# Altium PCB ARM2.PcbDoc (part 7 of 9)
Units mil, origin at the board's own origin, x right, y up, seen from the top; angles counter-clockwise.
Board outline 4700.79 x 3937.01 mil, 6 copper layers (Top Layer, GND02, ART03, ART04, PWR05, Bottom Layer); 689 components, 508 nets, 2312 pads, 1231 vias.

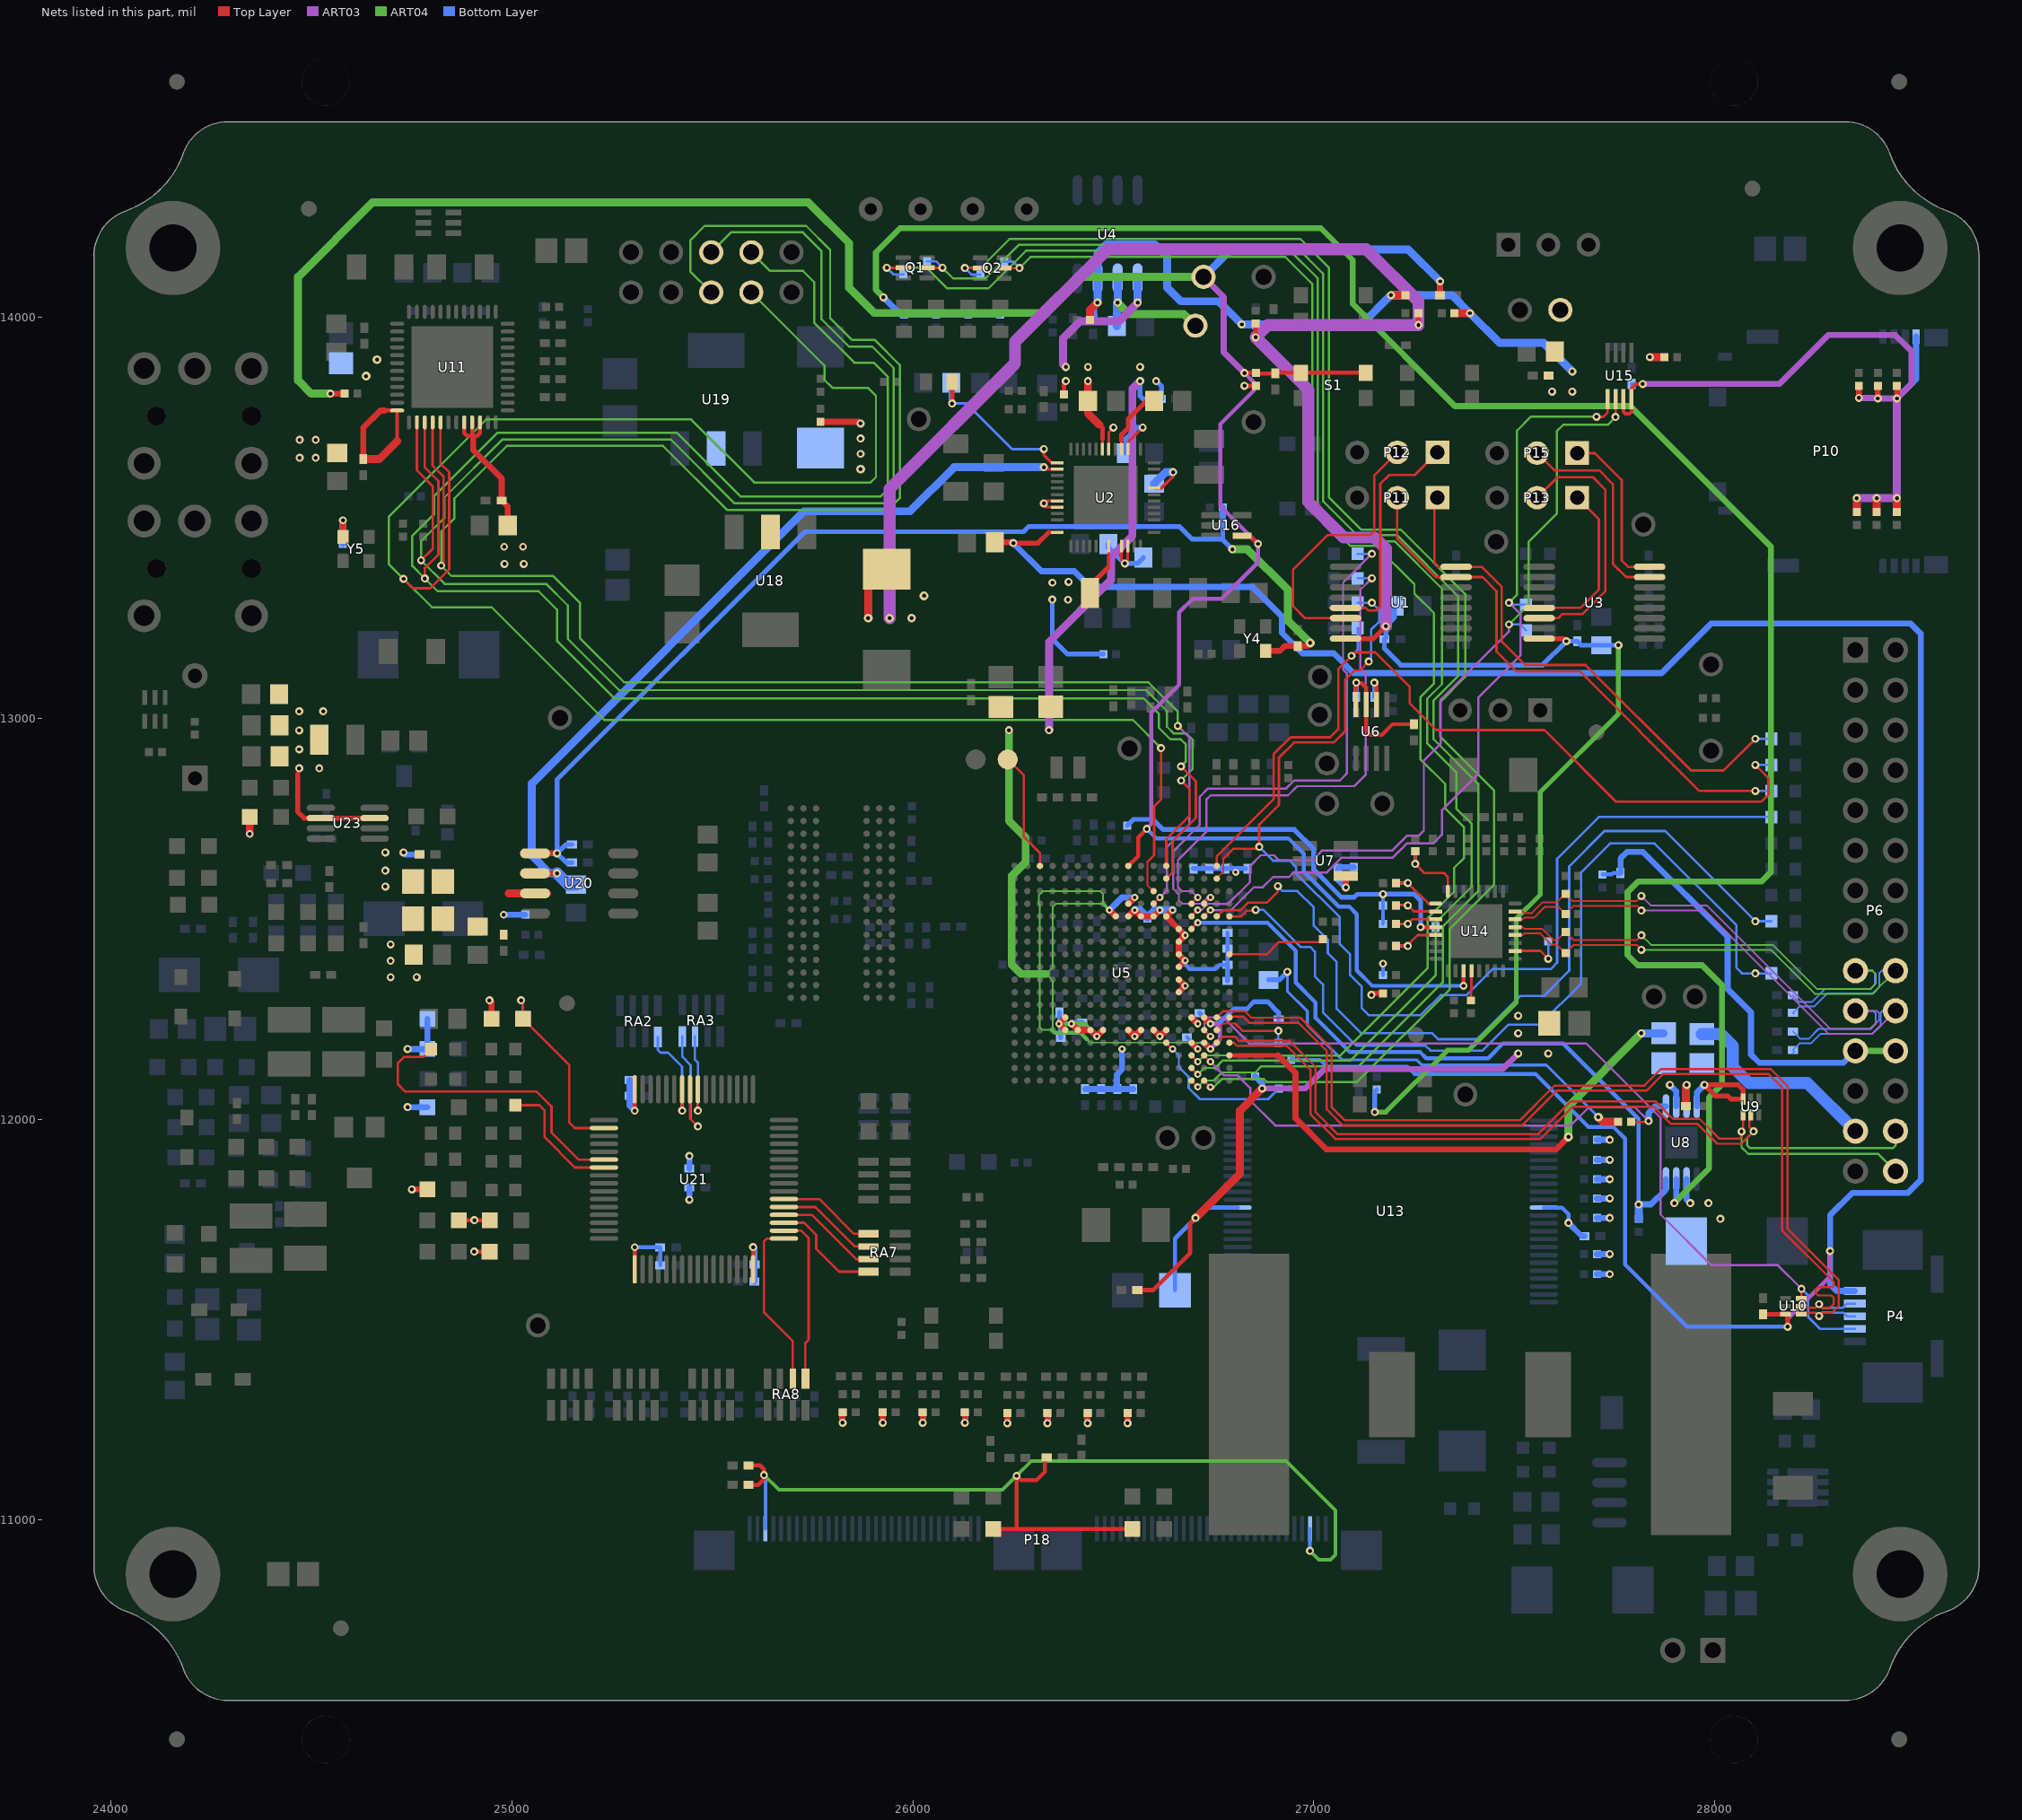
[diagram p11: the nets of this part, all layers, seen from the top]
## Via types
v1: diameter 20, hole 10, Top Layer to Bottom Layer, tented both sides, 870 vias
v2: diameter 18, hole 8, Top Layer to Bottom Layer, tented both sides, 273 vias
v3: diameter 22, hole 10, Top Layer to Bottom Layer, tented both sides, 64 vias
v4: diameter 20, hole 10, Top Layer to Bottom Layer, 18 vias
v5: diameter 22, hole 12, Top Layer to Bottom Layer, 4 vias
v6: diameter 22, hole 10, Top Layer to Bottom Layer, 1 vias
v7: diameter 39.37, hole 19.68, Top Layer to Bottom Layer, tented both sides, 1 vias

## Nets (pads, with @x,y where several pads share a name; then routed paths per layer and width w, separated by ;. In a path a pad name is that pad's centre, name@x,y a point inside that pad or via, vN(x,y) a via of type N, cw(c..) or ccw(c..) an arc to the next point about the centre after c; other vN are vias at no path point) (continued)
RI_H3: RA2.5 U21.58 | length 272.9
  Top Layer w6: v1(25424.84,12021.21) U21.58@25424.84,12074.41
  Bottom Layer w6: RA2.5@25364.24,12204.63 25364.24,12172.76 25371,12166 25390,12166 25424.84,12131.16 v1(25424.84,12021.21)
RI_H4: RA3.8 U21.57 | length 341.2
  Top Layer w6: U21.57@25444.53,12074.41 25444.53,12001.52 v1(25464.21,11981.84)
  Bottom Layer w6: RA3.8@25425.51,12206.26 25425.51,12155.49 25446,12135 25446,12000.05 v1(25464.21,11981.84)
RI_H5: RA3.7 U21.56 | length 241.2
  Top Layer w6: v1(25464.21,12021.21) U21.56@25464.21,12074.41
  Bottom Layer w6: RA3.7@25457.01,12206.26 25457.01,12148.52 25464.21,12141.32 v1(25464.21,12021.21)
RLH: R195.2 U21.7 | length 324.5
  Top Layer w6: R195.2@25008.92,12035 25068.62,12035 25082,12021.62 25082,11955 25157.47,11879.53 U21.7@25229.96,11879.53
RO_H0: RA7.1 U21.38 | length 246.7
  Top Layer w6: U21.38@25678.78,11800.79 25766.72,11800.79 25853.27,11714.24 RA7.1@25889.63,11714.24
RO_H1: RA7.2 U21.37 | length 251.6
  Top Layer w6: U21.37@25678.78,11781.1 25757.38,11781.1 25855.73,11682.75 RA7.2@25889.63,11682.75
RO_H2: RA7.3 U21.36 | length 256.5
  Top Layer w6: U21.36@25678.78,11761.42 25748.58,11761.42 25858.75,11651.25 RA7.3@25889.63,11651.25
RO_H3: RA7.4 U21.35 | length 281.4
  Top Layer w6: U21.35@25678.78,11741.73 25728.82,11741.73 25759.53,11711.02 25759.53,11676.77 25816.54,11619.76 RA7.4@25889.63,11619.76
RO_H4: RA8.1 U21.34 | length 423.2
  Top Layer w6: U21.34@25678.78,11722.05 25722.09,11722.05 25740.27,11703.87 25740.27,11449.9 25732.24,11441.87 RA8.1@25732.24,11352.99
RO_H5: RA8.2 U21.33 | length 424.6
  Top Layer w6: U21.33@25678.78,11702.36 25636,11702.36 25629.15,11695.51 25629.15,11517.48 25700.75,11445.87 RA8.2@25700.75,11352.99
RS232_0_RXD: P13.1 U3.13 | length 419.3
  Top Layer w6: U3.13@27562.07,13275.19 27665.19,13275.19 27711,13321 27711,13496 P13.1@27657,13550
RS232_0_TXD: P13.2 U3.14 | length 650.4
  Top Layer w6: P13.2@27557,13550 27608,13601 27696,13601 27727,13570 27727,13316 27671,13260 27620.4,13260 27610,13249.6 U3.14@27562.07,13249.6
RS232_1_RXD: P11.1 R248.1 U1.8 | length 1333.1
  Top Layer w6: P11.1@27308.26,13550 27301,13542.74 27301,13388 27311.45,13377.55 U1.8@27355,13377.55 27419.07,13377.55 27469,13327.62 27469,13190.62 27527,13132.62 27677.85,13132.62 27940.96,12869.52 28022.15,12869.52 v1(28101.26,12948.62)
  Bottom Layer w6: v1(28101.26,12948.62) R248.1@28141.34,12948.62
RS232_1_TXD: P11.2 R250.1 U1.7 | length 1387
  Top Layer w6: P11.2@27210.82,13550 P11.2@27208.26,13550 27208.26,13447.44 27303.74,13351.96 U1.7@27355,13351.96 27420.66,13351.96 27456,13316.62 27456,13165.89 27505.27,13116.62 27663.47,13116.62 27961.47,12818.62 v1(28101.26,12818.62)
  Bottom Layer w6: v1(28101.26,12818.62) R250.1@28141.34,12818.62
RS232_2_RXD: P12.1 U1.13 | length 573.5
  Top Layer w6: U1.13@27079.41,13275.19 27129.32,13275.19 27135.57,13268.94 27155.86,13268.94 27166,13279.08 27166,13584.45 27188.12,13606.57 27251.83,13606.57 P12.1@27308.26,13663
RS232_2_TXD: P12.2 U1.14 | length 698.8
  Top Layer w6: U1.14@27081.01,13248 U1.14@27079.41,13249.6 26978.4,13249.6 26948,13280 26948,13369.45 27035.55,13457 27141,13457 27151,13467 27151,13605.74 P12.2@27208.26,13663
RS232_5_RXD: P15.1 U3.8 | length 415.8
  Top Layer w6: P15.1@27657,13661 27701,13661 27768,13594 27768,13393 27783.45,13377.55 U3.8@27837.66,13377.55
RS232_5_TXD: P15.2 U3.7 | length 525.2
  Top Layer w6: P15.2@27557,13661 27600,13618 27712,13618 27746,13584 27746,13385 27779.04,13351.96 U3.7@27837.66,13351.96
RXD0/MODE0: R112.1 R128.2 U14.11 | length 136.9
  Top Layer w6: R128.2@27205,12487.33 v1(27234.67,12487.33) ; v1@27235.88,12488.55 v1(27234.67,12487.33) ; U14.11@27302.89,12497.33 U14.11@27304.11,12498.55 27245.88,12498.55 v1(27234.67,12487.33)
  Bottom Layer w6: R112.1@27205,12487.33 v1(27234.67,12487.33)
RXD1/MODE1: R114.1 R127.2 U14.10 | length 135
  Top Layer w6: R127.2@27205,12533.17 v1(27234.67,12533.17) 27249.58,12518.25 U14.10@27304.11,12518.25
  Bottom Layer w6: R114.1@27205,12533.17 v1(27234.67,12533.17)
RXD2/RMIISEL: R117.1 R126.2 U14.9 | length 150.3
  Top Layer w6: R126.2@27205,12589 v1(27234.67,12589) 27286.67,12537 U14.9@27304.11,12537
  Bottom Layer w6: R117.1@27205,12589 v1(27234.67,12589)
RXD3/PHYAD2: R116.1 R125.2 U14.8 | length 203.6
  Top Layer w6: R125.2@27253.11,12667.86 v1(27253.11,12636.6) 27275.71,12614 27290,12614 ; 27280,12614 27290,12614 ; U14.8@27334.16,12568 27334.16,12604.84 27325,12614 27290,12614
  Bottom Layer w6: v1(27253.11,12636.6) R116.1@27253.11,12667.86
RXDV: R129.2 U14.26 | length 133.9
  Top Layer w6: U14.26@27502.11,12419.75 27565.25,12419.75 v1(27585,12400)
  Bottom Layer w6: v1(27585,12400) R129.2@27585,12442.86
RXER/PHYAD0: R115.1 R133.2 U14.13 | length 139
  Top Layer w6: R133.2@27205,12432 v1(27234.67,12432) ; v1@27234.67,12434.5 27259.32,12459.15 U14.13@27304.11,12459.15
  Bottom Layer w6: R115.1@27205,12432 v1(27234.67,12432)
RXN: C138.1 P6.20 R121.1 U14.30 | length 1453.3
  Top Layer w4.4: U14.30@27502.11,12498.55 27521,12498.55 27524.9,12502.45 27548.93,12502.45 27575.58,12529.1 27610.62,12529.1 R121.1@27627.72,12512 27647.62,12531.91 27805.65,12531.91 v1(27817.12,12520.43)
  ART03 w4.3: v1(27817.12,12520.43) 27976.05,12520.43 28283.24,12213.23 28393.9,12213.23 P6.20@28450.94,12270.28
  Bottom Layer w4.4: C138.1@28195,12165 C138.1@28198.9,12168.9 ; C138.1@28195,12172.8 28211.26,12189.06 28239.75,12189.06 28263.92,12213.23 28392.89,12213.23 28413.78,12234.12 28413.78,12266.51 28417.55,12270.28 P6.20@28450.94,12270.28
RXP: C137.1 P6.19 R120.1 U14.31 | length 1475.1
  Top Layer w4.4: U14.31@27502.11,12518.25 27521,12518.25 27524.9,12514.35 27544,12514.35 27570.65,12541 27606.72,12541 R120.1@27627.72,12562 27645.91,12543.81 27804.36,12543.81 v1(27817.12,12556.57)
  ART03 w4.3: v1(27817.12,12556.57) 27840.97,12532.73 27981.14,12532.73 28288.34,12225.53 28388.8,12225.53 28409.73,12246.45 28409.73,12265.07 28404.52,12270.28 P6.19@28350.94,12270.28
  Bottom Layer w4.4: C137.1@28195,12218.62 28212.67,12200.96 28234.82,12200.96 28258.99,12225.13 28387.96,12225.13 28401.88,12239.05 28401.88,12263.17 28394.78,12270.28 P6.19@28350.94,12270.28
SEL_I_DATA: R202.2 R207.1 U21.2 | length 495.7
  Top Layer w6: v1(25023.37,12296.63) 25028.37,12291.63 R202.2@25028.37,12250 25143,12135.37 25143,11992 25157.05,11977.95 U21.2@25229.96,11977.95
  Bottom Layer w6: v1(25023.37,12296.63) 25028.37,12291.63 R207.1@25028.37,12250
SPI1_CS0: TP25.1 U5.C12 U11.41 | length 5157.1
  Top Layer w4.4: 26585.12,12641.57 26585.12,12584.32 U5.C12@26600.72,12568.72
  Top Layer w6: v1(24730.12,13347.57) 24753.58,13324.12 24796.67,13324.12 24844,13371.45 24844,13613.62 24822.06,13635.57 24822.06,13737.41 U11.41@24822.47,13737.82 ; 26585.12,12641.57 26602.12,12658.57 26602.12,12780.3 26619.12,12797.3 v1(26619.12,12925.57)
  ART04 w5.5: TP25.1@25597.5,14062 25780.07,13879.43 25780.07,13843.6 25799.78,13823.89 25888.05,13823.89 25908.19,13803.76 25908.19,13601.12 25894.82,13587.75 25604.7,13587.75 25447.56,13744.89 24936.44,13744.89 24693.12,13501.57 24693.12,13384.57 v1(24730.12,13347.57) 24801.19,13276.51 24950.19,13276.51 25231.12,12995.57 26549.12,12995.57 v1(26619.12,12925.57)
SPI1_D0: TP26.1 U5.B13 U11.39 | length 5258.4
  Top Layer w6: v1(24783.12,13348.62) 24783.12,13374.57 24817,13408.45 24817,13591.62 24783.1,13625.52 U11.39@24783.1,13737.82 ; U5.B13@26632.22,12600.22 26648.02,12616.02 26648.02,12692.87 26706.12,12750.97 26706.12,12842.58 v1(26668.9,12879.8)
  ART04 w5.5: TP26.1@25597.5,14162 25643.93,14115.57 25726.37,14115.57 25754.18,14087.76 25754.18,13986.52 25854.11,13886.59 25902.86,13886.59 25938.04,13851.41 25938.04,13571.01 25919.41,13552.38 25571.44,13552.38 25412.45,13711.38 24963.8,13711.38 24806.12,13553.7 24806.12,13508.57 24752.12,13454.57 24752.12,13379.62 v1(24783.12,13348.62) 24815.44,13316.31 25067.17,13316.31 25112.64,13270.84 25112.64,13193.05 25256.2,13049.5 26575.8,13049.5 26613.53,13011.77 26613.53,12976.59 26642.55,12947.57 26668.12,12947.57 26681.12,12934.57 26681.12,12892.03 v1(26668.9,12879.8)
SPI1_D1: TP27.1 U5.D12 U11.40 | length 5625.4
  Top Layer w6: U11.40@24802.79,13737.82 24802.79,13629.83 24830,13602.62 v1@24830,13380.57 ; U5.D12@26600.72,12537.23 v2(26616.47,12552.98)
  ART03 w5.5: v2(26616.47,12552.98) 26634.12,12570.64 26634.12,12679.57 26690.12,12735.57 26690.12,12951.57 v1(26661.12,12980.57)
  ART04 w5.5: TP27.1@25497.5,14062 25445.12,14114.38 25445.12,14191.57 25481.12,14227.57 25734.11,14227.57 25794.1,14167.59 25794.1,13997.6 25847.88,13943.82 25904.88,13943.82 25967.88,13880.81 25967.88,13548.66 25938.77,13519.55 25536.93,13519.55 25377.05,13679.42 24987.98,13679.42 24857.06,13548.51 24857.06,13498.64 24824.12,13465.7 v1(24824.12,13380.57) 24850.17,13354.53 25103.35,13354.53 25170.7,13287.19 25170.7,13199 25280.1,13089.6 26587.83,13089.6 26661.12,13016.31 v1(26661.12,12980.57)
SPI1_SCLK: TP28.1 U5.A13 U11.38 | length 5378.3
  Top Layer w6: U11.38@24763.42,13737.82 24763.42,13618.2 24803.21,13578.41 24803.21,13422.83 v1(24774,13393.62) ; U5.A13@26632.22,12631.72 26632.22,12698.39 26690.12,12756.3 26690.12,12823.72 v1(26669.32,12844.53)
  ART04 w5.5: TP28.1@25497.5,14162 25547.07,14211.57 25725.9,14211.57 25772.75,14164.72 25772.75,13994.95 25841.12,13926.57 25899.12,13926.57 25952.7,13873 25952.7,13560.87 25927.56,13535.73 25555.87,13535.73 25396.31,13695.29 24976.84,13695.29 24832.17,13550.62 24832.17,13499.53 24774,13441.36 v1(24774,13393.62) 24832.58,13335.04 25085.81,13335.04 25139.92,13280.93 25139.92,13197.78 25267.64,13070.06 26581.91,13070.06 26633.87,13018.1 26633.87,12978.83 26651.12,12961.57 26682.88,12961.57 26697.67,12946.79 26697.67,12872.88 v1(26669.32,12844.53)
SYS_5V: C7.2 C8.2 C10.2 C13.2 C17.1 C34.1 C200.1 R71.1 R72.1 R73.1 R74.1 TP12.1 U2.2 U2.7 U2.8 U2.21 U2.22 U2.32 U2.39 U2.42 U4.2 U8.2 U8.3 U20.2 | length 8396.9
  Top Layer w7: v1(26327,13626) 26332.13,13620.87 U2.2@26359.99,13620.87 ; U2.8@26359.99,13526.38 26331.62,13526.38 26327,13531 v1(26327,13536) 26333.13,13542.13 U2.7@26359.99,13542.13 ; U2.42@26488.92,13671.06 26488.92,13713.42 v1(26500.44,13724.93) ; U2.21@26520.42,13428.94 26520.42,13394.58 v1(26529,13386) 26536.17,13393.17 U2.22@26536.17,13428.94 ; U2.39@26536.42,13671.31 U2.39@26536.17,13671.06 26536.17,13687.67 v1(26573.44,13724.93)
  Top Layer w8: U2.32@26602.12,13573.62 26619.71,13573.62 26649.35,13603.26 v1(26649.35,13613.82)
  Top Layer w15: U20.2@25058,12613 v1(25113,12613)
  ART04 w15: v1(25927.12,14049.57) 25908.12,14068.57 25908.12,14161.57 25968.52,14221.97 27017.73,14221.97 27097.12,14142.57 27097.12,14033.57 27352.12,13778.57 27789.12,13778.57 28140.37,13427.32 28140.37,12616.72 28116.22,12592.57 27808.67,12592.57 27782.47,12566.36 27782.47,12409.13 27807.69,12383.91 27968.47,12383.91 28018.44,12333.94 28018.44,12087.36 27985.71,12054.64 27985.71,11877.16 v1(27899.12,11790.57)
  ART04 w20: v1(26510.92,14036.78) 26540.12,14007.57 26676.38,14007.57 TP12.1@26705,13978.95
  Bottom Layer w12: C8.2@26487.44,13433.94 26487.44,13425.57 26528,13385 v1(26529,13386) 26560.55,13386 C7.2@26575.12,13400.57 ; C13.2@26532,13661 26532,13698.34 26558.6,13724.93 v1(26573.44,13724.93)
  Bottom Layer w15: v1(25927.12,14049.57) 25969.84,14006.86 R72.1@25978.19,14006.86 R73.1@26058.19,14006.86 R74.1@26138.19,14006.86 R71.1@26218.19,14006.86 ; v1(27899.12,11790.57) 27904,11795.45 U8.3@27904,11850.37 ; U8.2@27929.6,11850.37 27929.6,11800.1 v1(27939.12,11790.57)
  Bottom Layer w20: v1(25113,12613) 25094.15,12613 25050,12657.15 25050,12837.05 25728.96,13516.01 25993.09,13516.01 26103.08,13626 v1(26327,13626) ; C17.1@26509.54,13977.88 26509.54,14035.41 v1(26510.92,14036.78) U4.2@26510.92,14096.88 ; C10.2@26602,13585 26630.82,13613.82 v1(26649.35,13613.82)
  Bottom Layer w30: v1(25113,12613) 25141,12585 C200.1@25160,12585
  other v1: 28014.12,11751.57 27984.12,11790.57
SYS_RESETN: C24.1 C30.1 R14.2 R44.1 S1.2 S1.4 TP14.1 U5.A10 U14.19 U16.4 | length 6846.6
  Top Layer w10: U5.A10@26537.73,12631.72 26562.12,12656.12 26562.12,12702.62 v1(26583.56,12724.06) ; R14.2@26855.73,13861.14 26856.87,13860 C24.1@26903.73,13860 26905.23,13861.5 S1.2@26968.02,13861.5 S1.4@27129.44,13861.5 ; v1(27373.56,12332.56) U14.19@27373.56,12370
  Top Layer w12: U16.4@26821.37,13455.41 26840.41,13455.41 v1(26861,13434.82) ; v1(26827.14,13861.14) R14.2@26855.73,13861.14
  Top Layer w15: v1(24548,13809.41) R44.1@24582.86,13809.41 ; C30.1@27315,14055 v1(27315,14089.45)
  ART03 w10: v1@26583,12724.62 v1@26583.56,12725.18 ; v1(26583.56,12724.06) v1@26583.56,12725.18 ; v1(26827.14,13861.14) 26851.12,13837.16 26851.12,13817.57 26767.12,13733.57 26767.12,13528.69 v1(26861,13434.82) 26861,13388.45 26770.55,13298 26698.12,13298 26664.2,13264.07 26664.2,13083.5 26595.12,13014.43 26595.12,12736.75 v1@26583.56,12725.18
  ART03 w15: TP14.1@26725.12,14100.57 26775.63,14050.06 26775.63,13912.65 v1(26827.14,13861.14)
  ART04 w20: v1(24548,13809.41) 24500.28,13809.41 24467.12,13842.57 24467.12,14100.57 24653.12,14286.57 25739.12,14286.57 25841.12,14184.57 25841.12,14073.57 25904.12,14010.57 26325.12,14010.57 26415.12,14100.57 TP14.1@26725.12,14100.57
  Bottom Layer w10: v1@26583,12724.62 v1(26583.56,12724.06) 26607.07,12700.55 26936.45,12700.55 26975,12662 26975,12617.67 27062.68,12529.99 27088.63,12529.99 27107.59,12511.03 27107.59,12371.03 27146.06,12332.56 v1(27373.56,12332.56)
  Bottom Layer w20: TP14.1@26725.12,14100.57 26793.66,14169.11 27235.34,14169.11 v1(27315,14089.45)
TCT_RCT: C141.1 P6.21 P6.22 R137.1 | length 1149.3
  ART04 w15: P6.21@28350.94,12170.28 P6.22@28450.94,12170.28
  Bottom Layer w10: R137.1@27720,12610.14 27743,12610.14 27746.86,12614 C141.1@27765,12614 C141.1@27761.14,12610.14
  Bottom Layer w15: C141.1@27765,12614 27765,12650 27781.62,12666.62 27821,12666.62 28032,12455.62 28032,12324.7 28090.12,12266.57 28090.12,12161.57 28111.12,12140.57 28321.24,12140.57 P6.21@28350.94,12170.28
TESTOUT: TP3.1 U5.A3 | length 298.5
  Top Layer w6: TP3.1@26237,12897 26277,12857 26277,12704 26317.26,12663.74 U5.A3@26317.26,12631.72
TXCLK: R134.2 U14.20 | length 74.4
  Top Layer w6: R134.2@27391.88,12296.2 27391.88,12319.25 27393.26,12320.62 U14.20@27393.26,12370
TXN: C140.1 P6.18 R123.1 U14.28 | length 1380.1
  Top Layer w4.4: U14.28@27502.11,12459.15 27521,12459.15 27524.9,12463.05 27564.95,12463.05 27592.9,12435.1 27606.62,12435.1 R123.1@27627.72,12414 27648.27,12434.55 27805,12434.55 v1(27817.12,12422.43)
  ART04 w4.3: v1(27817.12,12422.43) v1@27817.24,12422.31 ; v1@27819.28,12420.27 v1@27817.24,12422.31 ; P6.18@28450.94,12370.28 28393.5,12312.83 28249.45,12312.83 28139.97,12422.31 v1@27817.24,12422.31
  Bottom Layer w4.4: C140.1@28197.33,12262.67 C140.1@28195,12265 28210.86,12280.86 28247.99,12280.86 28280.36,12313.23 28394.8,12313.23 28410.87,12329.3 28410.87,12364.93 28416.21,12370.28 P6.18@28450.94,12370.28
TXP: C139.1 P6.17 R122.1 U14.29 | length 1381.7
  Top Layer w4.4: U14.29@27502.11,12478.85 27521,12478.85 27524.9,12474.95 27569.88,12474.95 27597.83,12447 27607.72,12447 R122.1@27627.72,12467 27648.27,12446.45 27805,12446.45 v1(27817.12,12458.57)
  ART04 w4.3: v1(27817.12,12458.57) 27841.09,12434.61 28145.06,12434.61 28254.55,12325.13 28388.33,12325.13 28401.92,12338.71 28401.92,12361.72 28393.36,12370.28 P6.17@28350.94,12370.28
  Bottom Layer w4.4: C139.1@28195,12308.62 28210.86,12292.76 28243.06,12292.76 28275.43,12325.13 28389.87,12325.13 28398.97,12334.23 28398.97,12364.66 28393.36,12370.28 P6.17@28350.94,12370.28
U5_H18: R28.1 U5.H18 | length 248.8
  Top Layer w6: U5.H18@26789.7,12411.24 26882.62,12411.24 26913.14,12441.76 27015.23,12441.76 R28.1@27022.72,12449.24
U5_R13: R160.1 U5.R13 | length 383.6
  Top Layer w6: U5.R13@26632.22,12190.77 v2(26647.97,12175.03)
  Bottom Layer w4.4: v2(26647.97,12175.03) 26663.47,12159.53 26663.47,12130.16
  Bottom Layer w6: 26663.47,12130.16 26688,12105.62 26688,12077.67 26715.67,12050 26886.31,12050 R160.1@26912.92,12076.61
UART0_RXD: R42.1 U5.E15 U15.6 | length 2088.8
  Top Layer w6: U5.E15@26695.21,12505.73 v2(26710.96,12521.48) ; v1(27752.83,13751.46) U15.6@27752.78,13795.57
  ART03 w4.4: v2(26710.96,12521.48) 26720.53,12521.48 26736.28,12537.23 26749.39,12537.23
  ART03 w5.5: 26749.39,12537.23 26786.78,12537.23 26841.12,12591.57 26841.12,12631.57 26867.78,12658.22 26900.48,12658.22 26912.83,12645.87 26996.42,12645.87 27020.12,12669.57 27195.12,12669.57 27232.12,12706.57 27261.17,12706.57 27274.55,12719.96 27274.55,12894.29 27317,12936.74 27317,13047 27487,13217 v1(27487,13234)
  ART04 w5.5: v1(27487,13234) 27536.12,13283.12 27536.12,13440.12 27606,13510 27606,13715.45 27622.12,13731.57 27732.94,13731.57 v1(27752.83,13751.46)
  Bottom Layer w6: v1@27487.06,13234.06 27514.28,13234.06 R42.1@27529.28,13219.06
UART0_TXD: R240.1 U5.E16 U15.5 | length 2109.2
  Top Layer w6: U5.E16@26726.7,12505.73 v2(26742.45,12521.48) ; v1(27705.31,13751.57) 27722.31,13751.57 27733.1,13762.36 U15.5@27733.1,13795.57
  ART03 w5.5: v2(26742.45,12521.48) 26794.03,12521.48 26850.92,12578.36 26872.92,12578.36 26898.62,12604.07 26938.62,12604.07 26950.12,12615.57 27033.12,12615.57 27070.12,12652.57 27197.12,12652.57 27232.12,12687.57 27297.98,12687.57 27319.73,12709.33 27319.73,12770.46 27411,12861.73 27411,13052 27516,13157 27516,13259 v1(27487,13288)
  ART04 w5.5: v1(27487,13288) 27507,13308 27507,13717.45 27541.12,13751.57 v1(27705.31,13751.57)
  Bottom Layer w6: v1@27487.13,13287.87 27492.13,13282.87 R240.1@27529.28,13282.87
UART1_RXD: R244.1 U5.D16 | length 1410.4
  Top Layer w6: U5.D16@26726.7,12537.23 v2(26742.45,12552.98)
  ART03 w4.4: 26649.12,12574.57 26663.47,12560.23 26663.47,12547.05 26673.04,12537.48 26719.48,12537.48 26734.98,12552.98 v2(26742.45,12552.98)
  ART03 w5.5: 26649.12,12574.57 26649.12,12667.57 26715.62,12734.07 26715.62,12804.07 26736.12,12824.57 26931.12,12824.57 26951.12,12844.57 27065.12,12844.57 27083.12,12862.57 27083.12,13111.57 27073.12,13121.57 27073.12,13338.12 v1(27145,13410)
  Bottom Layer w6: R244.1@27109.85,13410 v1(27145,13410)
UART1_TXD: R243.1 U5.D15 | length 1295.4
  Top Layer w6: U5.D15@26695.21,12537.23 v2(26710.96,12552.98)
  ART03 w4.4: 26661.36,12578.77 26671.6,12568.53 26695.65,12568.53 26711.08,12553.1 v2@26711.2,12552.98
  ART03 w5.5: 26661.36,12578.77 26661.36,12645.81 26732.12,12716.57 26732.12,12796.57 26743.12,12807.57 26936.12,12807.57 26959.12,12830.57 27101.12,12830.57 27129.12,12858.57 27129.12,13110.57 27116.12,13123.57 27116.12,13320 v1(27145,13348.87)
  Bottom Layer w6: R243.1@27109.85,13348.87 v1(27145,13348.87)
UART2_RXD: R33.1 R247.1 U5.A17 | length 2153.5
  Top Layer w6: U5.A17@26758.2,12631.72 26758.2,12655.97 26900.12,12797.89 26900.12,12910.52 26942.3,12952.7 27041.01,12952.7 27061.12,12972.82 27061.12,13122.57 v1(27094.12,13155.57) 27102.52,13163.97 27153.73,13163.97 27239.12,13078.57 27239.12,13037.57 27306.12,12970.57 27575.12,12970.57 27754.08,12791.62 28116,12791.62 28134,12809.62 28134,12850.88 v1(28101.26,12883.62)
  Bottom Layer w6: v1(27094.12,13155.57) 27109.85,13171.3 R33.1@27109.85,13225 ; v1(28101.26,12883.62) R247.1@28141.34,12883.62
UART2_TXD: R242.1 R249.1 U5.B17 | length 2917.2
  Top Layer w4.4: U5.B17@26758.2,12600.22 26774,12616.02 26774,12649.07
  Top Layer w6: 26774,12649.07 26799.2,12674.27 26859.05,12674.27 v1(26864.03,12679.25) 26864.03,12734.66 26913,12783.63 26913,12901.6 26950.74,12939.35 27049.96,12939.35 27078.25,12967.64 27078.25,13095.7 27101.12,13118.57 27114.12,13118.57 v1(27137.12,13141.57)
  Bottom Layer w6: v1(26864.03,12679.25) 26898.34,12644.95 26939.73,12644.95 26956.06,12628.61 26956.06,12612.61 27064.99,12503.69 27064.99,12436.34 27090.61,12410.71 27090.61,12359.06 27119.61,12330.06 27119.61,12277.06 27137.06,12259.61 27267.07,12259.61 27316.89,12309.42 27380.56,12309.42 27445.38,12374.25 27590.92,12374.25 27607,12390.32 27607,12649.62 27711,12753.62 R249.1@28141.34,12753.62 ; R242.1@27109.85,13287.87 v1(27145,13287.87) 27163.86,13269.02 27163.86,13241.58 27143.1,13220.82 27143.1,13147.55 v1(27137.12,13141.57)
UART4_RXD: R256.1 U5.E18 | length 2153.9
  Top Layer w6: U5.E18@26789.7,12505.73 26819.52,12505.73 26834.11,12520.33 26854.99,12520.33 26855.11,12520.44 v1(26855.11,12521.94)
  Bottom Layer w6: v1(26855.11,12521.94) 26874.75,12521.94 26967.22,12429.47 26991,12429.47 27003,12417.47 27003,12355.93 27023.15,12335.77 27023.15,12266.47 27106.01,12183.61 27278.39,12183.61 27291.06,12170.94 27420.71,12170.94 27485.67,12235.9 27564.28,12235.9 27667,12338.62 27667,12615.62 27739,12687.62 27850,12687.62 28054,12483.62 28054,12377.62 28068,12363.62 v1(28101.26,12363.62) R256.1@28141.34,12363.62
UART4_TXD: R252.1 U5.E17 | length 2156.1
  Top Layer w6: U5.E17@26758.2,12505.73 26759.1,12505.73 26774.4,12521.03 26816.8,12521.03 26835.71,12539.94 26882.67,12539.94 26910.65,12567.93 v1(26910.65,12581.15)
  Bottom Layer w6: v1(26910.65,12581.15) 26910.65,12580.83 26922.49,12569 26959.28,12569 27000,12528.28 27000,12482.62 27034.88,12447.75 27034.88,12413.88 27057.19,12391.56 27057.19,12275.05 27117.63,12214.61 27294.86,12214.61 27310.06,12199.41 27406.67,12199.41 27514.68,12307.42 27574.25,12307.42 27637,12370.17 27637,12630.62 27725,12718.62 27876.26,12718.62 v1(28101.26,12493.62) R252.1@28141.34,12493.62
UDH: R192.2 U21.6 | length 780.4
  Top Layer w6: R192.2@24799.08,12175 24779.08,12155 24731,12155 24716,12140 24716,12087 24734,12069 25062,12069 25099,12032 25099,11967 25166.79,11899.21 U21.6@25229.96,11899.21
USB0_DM: P4.2 U5.N18 U10.2 | length 2501.5
  Top Layer w5.5: U5.N18@26789.7,12253.76 26792.34,12256.4 26823.4,12256.4 26839.14,12240.66 26961.89,12240.66 27032.4,12170.15 27032.4,12024.54 27072.19,11984.75 27519.31,11984.75 27605.71,12071.15 27829.39,12071.15 27870.87,12112.63 28134.04,12112.63 28168.54,12078.14 28168.54,11721.9 28296.97,11593.47 28296.97,11585.04 28292.92,11580.99 28258.12,11580.99 28251.97,11574.84 28251.97,11566.64 28258.12,11560.49 28290.82,11560.49 28296.97,11554.34 28296.97,11539.44 28287.57,11530.04 28268.55,11530.04 v1(28259.97,11538.62) 28251.47,11530.12 28232.29,11530.12 28229.57,11532.84 U10.2@28218.65,11532.84
  Bottom Layer w5.5: v1(28259.97,11538.62) 28268.47,11530.12 28320.05,11530.12 28330.05,11540.12 P4.2@28349.64,11540.12
USB0_DP: P4.3 U5.N17 U10.1 | length 2503
  Top Layer w5.5: U5.N17@26758.2,12253.76 26773.34,12268.9 26828.58,12268.9 26844.32,12253.16 26967.07,12253.16 27044.9,12175.33 27044.9,12029.72 27077.37,11997.25 27514.13,11997.25 27600.53,12083.65 27824.21,12083.65 27865.69,12125.13 28139.22,12125.13 28181.04,12083.31 28181.04,11727.08 28309.47,11598.65 28309.47,11534.26 28292.75,11517.54 28268.39,11517.54 v1(28259.97,11509.12) 28251.47,11517.62 28233.15,11517.62 28228.69,11513.16 U10.1@28218.65,11513.16
  Bottom Layer w5.5: v1(28259.97,11509.12) 28268.47,11517.62 28320.37,11517.62 28329.37,11508.62 P4.3@28349.64,11508.62
USB0_ID: P4.4 U5.P16 U10.3 | length 2212.6
  Top Layer w6: U5.P16@26726.7,12222.27 v2(26742.45,12206.53) ; U10.3@28216.25,11552.52 28216.25,11553.3 v1(28216.25,11576.84)
  ART03 w4.4: v2(26742.45,12206.53) 26726.95,12222.03 26726.95,12245.95 26735,12254 26750,12254
  ART03 w5.5: 26750,12254 26774,12254 26839,12189 27679.12,12189 27864.73,12003.39 27864.73,11762.49 27991.62,11635.6 28157.49,11635.6 v1(28216.25,11576.84)
  Bottom Layer w6: v1(28216.25,11576.84) 28232.97,11560.12 28232.97,11506.84 28262.69,11477.12 P4.4@28349.64,11477.12
USB1_DM: P6.26 U5.R18 U9.2 | length 2056.9
  Top Layer w5.5: U5.R18@26789.7,12190.77 26800.55,12190.77 26808.52,12182.8 26932.7,12182.8 26991.73,12123.77 26991.73,12012.64 27053.8,11950.57 27565.12,11950.57 27646.04,12031.49 27847.5,12031.49 27890.75,11988.24 27957.05,11988.24 28006.61,11938.68 28066.01,11938.68 v1(28096.9,11969.57) 28086.57,11979.91 28086.57,11996.27 28090.12,11999.83 U9.2@28090.12,12010.89
  ART04 w5.5: v1(28096.9,11969.57) 28080.31,11952.97 28080.31,11935.59 28088,11927.9 28444.55,11927.9 28450.94,11934.3 P6.26@28450.94,11970.28
USB1_DP: P6.28 U5.R17 U9.1 | length 2059.3
  Top Layer w5.5: U5.R17@26758.2,12190.77 26773.25,12205.82 26803.18,12205.82 26813.7,12195.3 26939.57,12195.3 27004.23,12130.64 27004.23,12017.82 27058.98,11963.07 27559.95,11963.07 27640.86,12043.99 27852.68,12043.99 27895.93,12000.74 27962.23,12000.74 28011.79,11951.18 28060.83,11951.18 28066.81,11957.15 v1(28066.81,11969.29) 28070.44,11972.93 U9.1@28070.44,12010.89
  ART04 w5.5: v1(28066.81,11969.29) 28066.81,11930 28083,11913.81 28407.41,11913.81 P6.28@28450.94,11870.28
USB1_DRVVBUS: R53.1 U5.F15 U8.4 | length 1781.3
  Top Layer w6: U5.F15@26695.21,12474.24 v2(26710.96,12489.99)
  Bottom Layer w10: v2(26710.96,12489.99) 26884.96,12489.99 26955,12419.95 26955,12340.66 27004.58,12291.08 27004.58,12253.04 27090.54,12167.09 27265.59,12167.09 27280.66,12152.01 27435.06,12152.01 27471.62,12188.57 27622.12,12188.57 27810.12,12000.57 v1(27810.12,11787.57)
  Bottom Layer w15: v1(27810.12,11787.57) 27841.12,11787.57 27878.4,11824.85 U8.4@27878.4,11850.37
  Bottom Layer w20: R53.1@27810.12,11751.72 v1(27810.12,11787.57)
USB1_ID: R49.2 U5.P17 | length 198.6
  Top Layer w4.4: U5.P17@26758.2,12222.27 26774.93,12239 26804,12239
  Top Layer w6: 26804,12239 26822.6,12220.4 v1(26912,12220.4)
  Bottom Layer w6: R49.2@26911.57,12190.18 v1@26911.57,12220.4
USB1_OCN: R52.2 U5.T16 U8.5 | length 1347.4
  Top Layer w6: U5.T16@26726.7,12159.28 v2(26742.45,12143.54) ; R52.2@27791.27,11993.07 27832.62,11993.07 v1(27835.12,11995.57)
  ART03 w5.5: v2(26742.45,12143.54) 26776.98,12109 26810.43,12109 26841.63,12077.81 26841.63,12046.55 26903.74,11984.44 27640.74,11984.44 27686.3,12030 27800.7,12030 v1(27835.12,11995.57)
  Bottom Layer w15: v1(27835.12,11995.57) 27835.12,12015.57 27851.92,12032.37 U8.5@27878.4,12032.37
USB1_PWR: C35.1 FB7.1 FB8.2 U8.6 U8.7 U8.8 U9.6 | length 464
  Top Layer w12: v1(27974.12,12085.57) 28001.45,12058.25 28032.13,12058.25 28040.12,12050.26 U9.6@28070.44,12050.26 28070.44,12073.6 28058.47,12085.57 v1(27974.12,12085.57)
  Top Layer w20: C35.1@27927.7,12032.36 27927.7,12083.15 v1(27930.12,12085.57)
  Bottom Layer w10: v1@27929.6,12085.05 v1(27930.12,12085.57)
  Bottom Layer w15: v1(27888.12,12085.57) 27904,12069.7 U8.6@27904,12032.37 ; U8.7@27929.6,12032.37 v1@27929.6,12085.05 ; U8.8@27955.2,12032.37 27955.2,12066.65 v1(27974.12,12085.57)
USB1_VBUS: FB8.1 U5.T18 | length 1411.3
  Top Layer w12: U5.T18@26789.7,12159.28 26910.67,12159.28
  Top Layer w15: 26910.67,12159.28 26954.42,12115.53 26954.42,12002.28 27031.89,11924.82 27604.37,11924.82 v3(27635.12,11955.57)
  ART04 w20: v3(27635.12,11955.57) 27635.12,12032.45 v1(27817.12,12214.45)
  Bottom Layer w20: v1(27817.12,12214.45) FB8.1@27872.5,12214.45
USB_DC: C1.2 C36.1 P4.1 R159.1 U2.12 U10.6 | length 6528.7
  Top Layer w7.5: 26339.39,13463.39 U2.12@26359.99,13463.39
  Top Layer w11: 28131.29,11513.16 28176.31,11513.16 U10.6@28181.69,11513.16
  Top Layer w12: v1(26251,13436.62) 26312.62,13436.62 26339.39,13463.39 ; v1(28181.69,11482.56) U10.6@28181.69,11513.16
  Top Layer w15: C1.2@26205,13438.62 26249,13438.62 v1(26251,13436.62)
  ART03 w10: v1(28181.69,11482.56) 28181.69,11502 28287.57,11607.88 v1(28287.57,11671.24)
  Bottom Layer w10: R159.1@26943.85,12147.82 27015.86,12147.82 27033.06,12130.61 27233.6,12130.61 27251.06,12113.15 27552.85,12113.15 27684.84,11981.16 27746.71,11981.16 27776.12,11951.74 27776.12,11637.57 27931.14,11482.56 v1(28181.69,11482.56) ; R159.1@26946.14,12152.82 R159.1@26947.5,12151.46
  Bottom Layer w15: v1(26251,13436.62) 26321.05,13366.57 26403.12,13366.57 26442.12,13327.57 26847.1,13327.57 26921.06,13253.61 26921.06,13212.61 26972.1,13161.57 27050.12,13161.57 27098.94,13112.75 27867.3,13112.75 27990.61,13236.06 28488.85,13236.06 28513.63,13211.28 28513.63,11847.75 28482.35,11816.47 28343.68,11816.47 28287.57,11760.36 v1(28287.57,11671.24) 28287.57,11588.43 28304.39,11571.61 P4.1@28349.64,11571.61
USR0: Q1.2 R76.1 U5.V15 | length 3922.8
  Top Layer w6: Q1.2@26035.72,14123.22 v1(26074.19,14123.22) ; U5.V15@26695.21,12096.28 v2(26710.96,12080.54)
  ART04 w4.4: v2(26710.96,12080.54) 26726.96,12096.54 26750.91,12096.54
  ART04 w5.5: v1(26074.19,14123.22) 26100.79,14096.62 26181,14096.62 26265.2,14180.82 26951.33,14180.82 27023.44,14108.71 27023.44,13540.78 27107.34,13456.88 27207.37,13456.88 27359.73,13304.52 27359.73,13104.93 27299.09,13044.29 27299.09,12947.55 27410.12,12836.52 27410.12,12568.57 27321.96,12480.41 27321.96,12341.37 27112.54,12131.95 26869.63,12131.95 26854.26,12116.58 26770.96,12116.58 26750.91,12096.54
  Bottom Layer w6: R76.1@26035.72,14139.36 26058.05,14139.36 v1(26074.19,14123.22)
USR1: Q1.5 R77.1 U5.U15 | length 3995.4
  Top Layer w6: v1(25935.19,14123.22) Q1.5@25976.67,14123.22 ; U5.U15@26695.21,12127.78 v2(26710.96,12112.04)
  ART04 w4.4: v2(26710.96,12112.04) 26726.71,12127.79 26754.79,12127.79
  ART04 w5.5: v1(25935.19,14123.22) 26034.98,14123.22 26086.51,14071.69 26188.47,14071.69 26282.48,14165.7 26941.16,14165.7 27009.93,14096.93 27009.93,13532.07 27100.88,13441.12 27201.91,13441.12 27319.76,13323.27 27319.76,13085.21 27282.62,13048.07 27282.62,12938.4 27355.46,12865.56 27355.46,12774.85 27394.12,12736.19 27394.12,12580.57 27304.6,12491.04 27304.6,12359.04 27092.17,12146.61 26773.61,12146.61
  ART04 w6: 26754.79,12127.79 26773.61,12146.61
  Bottom Layer w6: v1(25935.19,14123.22) 25951.34,14107.07 R77.1@25976.67,14107.07
USR2: Q2.2 R78.1 U5.T15 | length 3512
  Top Layer w6: Q2.2@26227.72,14122.59 v1(26266.19,14122.59) ; U5.T15@26695.21,12159.28 v2(26710.96,12143.54)
  ART04 w4.4: v2(26710.96,12143.54) 26726.46,12159.04 26785.19,12159.04
  ART04 w5.5: v1(26266.19,14122.59) 26294.07,14150.46 26928.87,14150.46 26996,14083.33 26996,13524.79 27090.99,13429.8 27155.03,13429.8 27251.02,13333.81 27251.02,13310.94 27300.07,13261.89 27300.07,13086.63 27265.83,13052.39 27265.83,12897.63 27327.92,12835.54 27327.92,12774.71 27375.12,12727.5 27375.12,12651.75 27350.04,12626.66 27350.04,12567.19 27284.42,12501.57 27284.42,12377.04 27066.41,12159.04 26785.19,12159.04
  Bottom Layer w6: R78.1@26227.72,14138.73 26250.05,14138.73 v1(26266.19,14122.59)
USR3: Q2.5 R79.1 U5.V16 | length 3903.2
  Top Layer w6: v1(26130.19,14122.59) Q2.5@26168.67,14122.59 ; U5.V16@26726.7,12096.28 26726.7,12095.92 v2(26742.45,12080.18)
  ART04 w5.5: v1(26130.19,14122.59) 26168.96,14122.59 26241.54,14195.17 26966.43,14195.17 27037.59,14124.01 27037.59,13550.93 27118.1,13470.42 27216.91,13470.42 27377.69,13309.64 27377.69,13103.16 27315.56,13041.04 27315.56,12953.74 27449.81,12819.49 27449.81,12585.26 27339.09,12474.53 27339.09,12323.71 27108.06,12092.68 26882.79,12092.68 26875.25,12100.22 26770.93,12100.22 26750.89,12080.18 v2(26742.45,12080.18)
  Bottom Layer w6: v1(26130.19,14122.59) 26146.34,14106.44 R79.1@26168.67,14106.44
VBUS: FB7.2 P6.25 | length 513.7
  Bottom Layer w30: FB7.2@27968,12212.45 28015.25,12212.45 28045.12,12182.57 28045.12,12130.57 28085.12,12090.57 28230.65,12090.57 P6.25@28350.94,11970.28
VCCD: C208.1 C209.1 C210.1 C211.1 C212.1 C213.1 C214.1 C215.1 C216.1 C217.1 C218.1 C219.1 C230.1 FB12.2 P18.3 P18.60 R146.1 R147.1 R183.1 R193.1 R194.1 R202.1 R203.1 R204.1 R205.1 R206.1 U21.17 U21.32 U21.64 | length 3534
  Top Layer w10: R183.1@24868.37,11748 v1(24906.92,11748) R205.1@24945,11748 ; v1(24906.55,11670) R204.1@24944.63,11670 ; U21.17@25306.73,11625.59 v1(25306.73,11680.79) ; v1(25306.73,12021.21) U21.64@25306.73,12074.41 ; C219.1@25590.72,11087.73 25614.28,11087.73 25629,11102.45 v1(25629,11112.62) 25629,11126.7 25618.97,11136.73 C216.1@25590.72,11136.73 ; U21.32@25602.01,11625.59 v1(25602.01,11681.01) ; R146.1@26200.39,10978.27 26259,10978.27 ; C211.1@26334,11156.62 26329,11151.62 26329,11120.15 26308.42,11099.57 26270.05,11099.57 v1(26259,11110.62) 26259,10978.27 ; R147.1@26548.08,10978.27 26259,10978.27
  Top Layer w15: v1(24751,11825) R206.1@24789.63,11825 ; v1(24944.63,12296.63) 24949.63,12291.63 R202.1@24949.63,12250
  ART04 w9: v1(25629,11112.62) 25666.05,11075.57 26223.95,11075.57 v1(26259,11110.62) 26295.95,11147.57 26931.12,11147.57 27054.12,11024.57 27054.12,10913.57 27042.12,10901.57 27012.45,10901.57 v1(26990.78,10923.24)
  Bottom Layer w9: P18.3@25632.52,10978.27 v1@25632.53,11112.62 ; v1(26990.78,10923.24) P18.60@26990.79,10978.27
  Bottom Layer w10: v1(25306.73,11680.79) 25306.95,11680.57 C230.1@25370.12,11680.57 C218.1@25370.12,11635.57
  Bottom Layer w15: v1(24730,12665) 24735,12660 C215.1@24770,12660 ; v1(24740,12030) R193.1@24789.63,12030 ; v1(24740,12175) R194.1@24789.63,12175 R203.1@24789.63,12250 ; C209.1@25294,12098 C210.1@25294,12058 25294,12033.94 v1(25306.73,12021.21) ; v1(25443,11799) C214.1@25443,11830 ; C217.1@25443,11877 v1(25443,11908) ; v1(25602.01,11681.01) 25605.37,11677.65 C208.1@25605.37,11638 25605,11637.63 C213.1@25605,11595
  other v1: 24685,12580 24685,12620 24685,12665
VCCD_3V3A: C205.2 C242.2 C243.2 C244.2 FB13.2 L5.1 R213.1 U23.3 U23.6 | length 335.8
  Top Layer w12: 24466,12861.5 24466,12767 24482.2,12750.8 U23.6@24524.07,12750.8 U23.3@24657.93,12750.8
  Top Layer w20: v1(24346.63,12711.37) R213.1@24346.63,12754
  other v1: 24698,12354 24763,12354 24698,12395 24698,12436 24470,12875 24520,12875 24470,12922.33 24470,12969.67 24470,13017 24530,13017
VDCDC1: L1.2 R6.1 U2.19 | length 376.6
  Top Layer w7: 26485.95,13374.83 26488.92,13377.8 U2.19@26488.92,13428.94
  Top Layer w12: L1.2@26442.06,13312 26446.08,13334.96 26485.95,13374.83
  Bottom Layer w12: v1(26348.02,13295.99) 26348.02,13197.68 26385.7,13160 R6.1@26475.12,13160 ; v1(26387.12,13295.57) v1@26387.12,13296.12
  other v1: 26348.24,13338.01 26388.45,13339.82
VDD_1V8: C14.2 C78.1 C86.1 C88.1 FB1.1 FB2.2 R9.2 U2.40 U5.D10 U5.E9 U5.N16 U5.R16 | length 4021
  Top Layer w7: U2.40@26520.42,13671.06 26520.42,13693
  Top Layer w12: 26520.42,13693 26520.42,13707.03 26537.12,13723.73 26537.12,13745.57 26585.05,13793.5 26599.5,13793.5 C14.2@26602,13796
  Top Layer w16: v2(26490.48,12521.48) U5.E9@26506.23,12505.73 ; U5.D10@26537.73,12537.23 v2(26553.48,12552.98) ; U5.R16@26726.7,12190.77 v2(26742.45,12175.03) ; U5.N16@26726.7,12253.76 v2(26742.45,12238.02)
  Top Layer w40: FB2.2@26335,13027.6 FB2.2@26336,13028.6
  ART03 w10: v2(26742.45,12175.03) 26766,12198.58 26766,12230 26757.98,12238.02 v2(26742.45,12238.02)
  ART03 w20: v1(26340,12970) 26340,13189.75 26494.49,13344.24 26494.49,13401.15 26547.76,13454.41 26547.76,13821.76 v1(26567,13841)
  ART04 w4.4: 26347.5,12222.5 26344.9,12222.5 ; 26435,12199 26442.97,12191.03 26720.6,12191.03 26736.6,12175.03 v2(26742.45,12175.03) ; 26344.9,12222.5 26349,12226.6 26349,12346.1 26332.9,12362.2 26349,12378.3 26349,12528.8 26357.4,12537.2 26474.76,12537.2 26474.76,12561.24 26467.5,12568.5 26324.5,12568.5 26314,12558 26314,12538 26317.01,12534.99 26317.01,12362.22 26317,12228 26322.5,12222.5 26344.9,12222.5
  ART04 w8: 26474.76,12537.2 v2(26490.48,12521.48)
  ART04 w10: v1@26339.6,12970.4 v1(26340,12970) ; 26347.5,12222.5 26354,12216 26418,12216 26435,12199
  ART04 w20: v1(26240,12970) 26240,12744.21 26281.44,12702.77 26281.44,12641.32 26246.66,12606.54 26246.66,12385.66 26270.12,12362.2 26317,12362.2 26332.9,12362.2
  Bottom Layer w4.4: 26696.98,12191 26720.86,12191
  Bottom Layer w10: C78.1@26683.98,12204 26696.98,12191 ; 26720.86,12191 26726.47,12191 v2(26742.45,12175.03)
  Bottom Layer w12: v1(26567,13841) 26567,13803 26574,13796 R9.2@26620.86,13796 26620.86,13827.14 v1(26607,13841) ; C86.1@26715.45,12264.52 26715.95,12264.52 v2(26742.45,12238.02) 26763.02,12238.02 26800,12275 26833.06,12275 26851.06,12293 26885,12293 26912.38,12265.62 C88.1@26912.38,12249
  Bottom Layer w16: v2(26490.48,12521.48) 26521.98,12552.98 v2(26553.48,12552.98)
  other v1: 26567,13876
VDD_1V8B: C191.1 C192.2 C198.1 R35.1 U11.36 U19.2 | length 461.5
  Top Layer w10: 24682.73,13767.35 U11.36@24714.2,13767.35 24714.2,13690.65
  Top Layer w15: C191.1@24629.73,13646.35 24629.73,13724.35 24672.73,13767.35 24682.73,13767.35 ; R35.1@25770,13738.98 25866.02,13738.98 v1(25870,13735)
  Top Layer w20: C191.1@24629.73,13646.35 24669.9,13646.35 24714.2,13690.65
  other v1: 24471.1,13649.35 24511.1,13649.35 25870,13659.19 24471.1,13694.35 24511.1,13694.35 25870,13697.47
  other v6: 25870,13621.26
VDD_3V3A: C15.2 C27.1 C37.1 C38.1 C56.2 C57.2 C58.1 C59.1 C60.2 C61.2 C66.1 C67.1 C68.2 C69.2 C70.2 C71.2 C72.2 C73.2 C74.2 C75.2 C76.2 C77.1 C87.1 C152.1 C159.1 R1.1 R3.1 R4.1 R14.1 R52.1 R55.1 R56.1 R57.1 R58.1 R59.1 R60.1 R61.1 R62.1 R63.1 R64.1 R65.1 R66.1 R67.1 R68.1 R69.1 R70.1 R156.1 U2.43 U4.1 U5.E10 U5.E11 U5.E12 U5.E13 U5.F14 U5.G14 U5.H14 U5.J14 U5.K14 U5.L14 U5.N5 U5.N15 U5.P5 U5.P6 U5.P7 U5.P8 U5.P10 U5.P11 U5.P12 U5.P13 U5.R15 U6.6 U6.7 U6.8 U7.4 U20.1 Y4.4 | length 7049.7
  Top Layer w7: U2.43@26473.19,13671.06 26473.19,13697
  Top Layer w10: U6.8@27105.2,13034 v1@27105.2,13087.66 ; v1(27106.2,13088.66) v1@27105.2,13087.66 ; v1(27151.4,13088.66) 27156.4,13083.66 U6.6@27156.4,13034 ; C27.1@27241.4,12985 C27.1@27240,12985 ; C27.1@27250,12985 C27.1@27240,12985 ; v1@27105.2,13087.66 27106.2,13087.66 27119.54,13087.66 27130.8,13076.4 U6.7@27130.8,13034 27130.8,12969.4 27141.2,12959 27170.38,12959 27196.38,12985 C27.1@27240,12985
  Top Layer w12: R1.1@26377,13812.14 26377,13836 v1(26382,13841) ; 26465.08,13731.92 26473.19,13723.82 26473.19,13697 ; v1@26827,13829 v1(26827.14,13828.86) R14.1@26855.73,13828.86
  Top Layer w15: U20.1@25058,12663 v1(25113,12663) ; v1(25825.05,11243.08) R70.1@25825.05,11268.94 ; v1(25925.05,11243.08) R68.1@25925.05,11268.94 ; v1(26025.05,11243.08) R66.1@26025.05,11268.94 ; v1(26130.05,11243.08) R64.1@26130.05,11268.94 ; v1(26235.94,11241.7) R62.1@26235.94,11267.56 ; v1(26335.94,11241.7) R58.1@26335.94,11267.56 ; v1(26435.94,11241.7) R57.1@26435.94,11267.56 ; v1(26535.94,11241.7) R56.1@26535.94,11267.56 ; U5.E13@26632.22,12505.73 U5.F14@26663.71,12474.24 ; Y4.4@26880,13168 26916,13168 26928,13180 C159.1@26960,13180 26983.55,13180 v3(26991.12,13187.57) ; v1(27080,12578) U7.4@27080,12606.5
  Top Layer w16: U5.P5@26380.25,12222.27 v2(26364.51,12238.02) U5.N5@26380.25,12253.76 ; v2(26395.99,12238.02) U5.P6@26411.74,12222.27 U5.P7@26443.24,12222.27 v2(26458.99,12206.53) U5.P8@26474.74,12222.27 ; U5.P10@26537.73,12222.27 v2(26553.48,12206.53) U5.P11@26569.22,12222.27 ; U5.E10@26537.73,12505.73 v2(26553.48,12521.48) U5.E11@26569.22,12505.73 U5.E12@26600.72,12505.73 v2(26616.47,12521.48) ; U5.P12@26600.72,12222.27 v2(26616.47,12206.53) U5.P13@26632.22,12222.27 ; U5.E13@26632.22,12505.73 v2(26647.97,12521.48) ; U5.L14@26663.71,12316.76 v2(26679.46,12332.51) U5.K14@26663.71,12348.25 ; U5.J14@26663.71,12379.75 v2(26679.46,12395.5) U5.H14@26663.71,12411.24 U5.G14@26663.71,12442.74 v2(26679.46,12458.49) U5.F14@26663.71,12474.24 ; U5.R15@26695.21,12190.77 v2(26710.96,12175.03) ; U5.N15@26695.21,12253.76 v2(26710.96,12238.02)
  Top Layer w20: C15.2@26437,13796 C15.2@26437,13791 ; v1(26437,13841) C15.2@26437,13791 ; 26465.08,13731.92 26437,13760 C15.2@26437,13791 ; v3(27709.78,12005.18) 27721.89,11993.07 R52.1@27758.98,11993.07
  ART03 w15: v2(26679.46,12458.49) v2@26680,12459.03
  ART03 w20: v1(26382,13876) 26374.54,13883.46 26374.54,13946.99 26417.12,13989.57 26513.71,13989.57 v1(26560.92,14036.78)
  ART04 w12: v2(26364.51,12238.02) v2(26395.99,12238.02) 26427.5,12238.02 v2(26458.99,12206.53)
  ART04 w20: v1(26797,13421) 26834.7,13421 26935.62,13320.07 26935.62,13243.07 v3(26991.12,13187.57)
  Bottom Layer w7: v1(26934,12367.62) 26934,12319.18 26984.03,12269.15 26984.03,12234.77 27071.19,12147.61 27257.06,12147.61 27269.74,12134.93 27580.03,12134.93 v3(27709.78,12005.18)
  Bottom Layer w10: v2(26679.46,12395.5) 26679.46,12385.54 26690,12375 26755,12375 26765,12385 C37.1@26785,12385 C74.2@26785,12425 C76.2@26785,12465
  Bottom Layer w12: C87.1@25150,12640 25136,12640 v1(25113,12663) ; C69.2@25150,12685 25135,12685 v1(25113,12663) ; C58.1@26366,12266 26366,12239.51 v2(26364.51,12238.02) 26369,12233.52 C38.1@26369,12203 ; v2(26395.99,12238.02) 26398.98,12241 C56.2@26423,12241 ; C60.2@26700,12625 C59.1@26740,12625 C75.2@26780,12625 26805.45,12625 ; R4.1@26773.14,13481 26773.14,13446.27 ; C66.1@26785,12345 C37.1@26785,12385 ; v1(26797,13421) 26773.14,13444.86 26773.14,13446.27 ; v2(26805.45,12615.97) 26805.45,12625 ; C61.2@26830,12625 26805.45,12625 ; C77.1@26887.42,12347.42 26913.8,12347.42 v1(26934,12367.62) ; C72.2@27106.2,13053 v1(27106.2,13088.66) ; C73.2@27151.4,13053 v1(27151.4,13088.66) ; v1(25113,12663) 25113,12846.82 25731.28,13465.1 26276.38,13465.1 26289.29,13478 26665,13478 26696.73,13446.27 26773.14,13446.27
  Bottom Layer w15: v1(25825.05,11243.08) R69.1@25825.05,11268.94 ; v1(25925.05,11243.08) R67.1@25925.05,11268.94 ; v1(26025.05,11243.08) R65.1@26025.05,11268.94 ; v1(26130.05,11243.08) R63.1@26130.05,11268.94 ; v1(26235.94,11241.7) R61.1@26235.94,11267.56 ; v1(26335.94,11241.7) R60.1@26335.94,11267.56 ; C71.2@26430,12075 C68.2@26470,12075 C57.2@26510,12075 ; v1(26435.94,11241.7) R59.1@26435.94,11267.56 ; v2(26521.99,12175.03) 26521.99,12123.99 26509,12111 26509,12076 C57.2@26510,12075 ; v1(26535.94,11241.7) R55.1@26535.94,11267.56 ; C67.1@26550,12075 C57.2@26510,12075 ; v1(27080,12578) 27060,12598 C152.1@27060,12625 27063.86,12628.86 R156.1@27100,12628.86
  Bottom Layer w16: R4.1@26773.14,13481 R3.1@26773.14,13526
  Bottom Layer w20: v2(26553.48,12521.48) 26566.47,12521.48 C70.2@26584.97,12502.98 26603.47,12521.48 v2(26616.47,12521.48) v2(26647.97,12521.48) ; v1(26560.92,14036.78) U4.1@26560.92,14096.88
  other v1: 26437,13876
VDD_3V3AUX: C18.1 D1.2 U2.1 | length 438.5
  Top Layer w7: v1(26327,13671) 26327,13656 26346.39,13636.61 U2.1@26359.99,13636.61
  Top Layer w12: v1(26098.36,13784.81) D1.2@26098.36,13838.62
  Bottom Layer w7: v1(26098.36,13784.81) 26134.19,13784.81 26248,13671 v1(26327,13671)
  Bottom Layer w12: C18.1@26095.86,13836.62 26095.86,13787.31 v1(26098.36,13784.81)
VDD_3V3B: C6.1 C20.1 C23.1 C29.1 C125.1 C135.1 C153.1 C154.1 C155.2 FB4.1 P10.4 R2.2 R11.1 R13.2 R15.2 R16.2 R23.1 R24.1 R29.2 R30.2 R31.2 R112.2 R113.2 R114.2 R119.1 R150.1 R151.1 R152.1 R153.1 R154.1 R155.1 R157.2 R158.1 R163.1 TP10.1 U4.3 U13.12 U13.37 U14.12 U15.7 U15.8 | length 6809.1
  Top Layer w9: U15.7@27772.42,13795.57 27772.42,13764.46 27777.31,13759.57 27787.31,13759.57 27792.12,13764.39 27792.12,13795.57 27792.12,13823.39 27802.31,13833.57 v1(27820.31,13833.57)
  Top Layer w10: v1(27266.67,12478.85) U14.12@27304.11,12478.85
  Top Layer w11: C125.1@26560,11573.62 26599.31,11573.62 26691.87,11666.18 26691.87,11740.49 v1(26705,11753.62)
  Top Layer w12: v1(27144,12310) 27148,12314 R119.1@27172.72,12314
  Top Layer w15: v1(28359.43,13798.56) R150.1@28359.43,13829.13 R150.1@28359.43,13830.27 ; v1(28406.71,13797.42) R155.1@28406.71,13829.13 ; v1(28454.43,13797.42) R151.1@28454.43,13829.13
  Top Layer w20: R11.1@26442.06,13992.88 26442.06,14017.92 v1(26460.92,14036.78) ; v1(26705,11753.62) 26816.15,11864.77 26816.15,12021.15 v1(26871.61,12076.61) ; v1(27192.55,14055) R23.1@27228.86,14055 ; R24.1@27358.7,14010 R24.1@27351.14,14010 v1(27389.7,14010) ; v1(27838.12,13900.57) R157.2@27873.98,13900.57 ; R154.1@28354.12,13514.57 v1(28354.12,13548.57) ; R153.1@28404.12,13514.57 v1(28404.12,13548.57) ; R152.1@28454.12,13514.57 v1(28454.12,13548.57)
  ART03 w15: v1(26871.61,12076.61) 26978.62,12076.61 27027.26,12125.25 27471.25,12125.25 v1(27510,12164) ; v1(27820.31,13833.57) 28161.12,13833.57 28283.12,13955.57 28450.12,13955.57 28491.12,13914.57 28491.12,13834.11 v1(28454.43,13797.42) ; v1(28359.43,13798.56) 28405.57,13798.56 v1(28406.71,13797.42) 28453.82,13797.42 v1@28454.12,13797.11
  ART03 w20: v1(28354.12,13548.57) v1(28404.12,13548.57) v1(28454.12,13548.57) 28454.12,13797.11 v1(28454.43,13797.42)
  Bottom Layer w9: C155.2@27792.62,13833.57 v1(27820.31,13833.57)
  Bottom Layer w10: R113.2@27172.72,12359.83 v1(27172.72,12387.95) ; R112.2@27172.72,12487.33 R114.2@27172.72,12533.17 v1(27172.72,12561.28) ; v1(27266.67,12478.85) 27266.97,12479.15 C135.1@27304.11,12479.15 ; U13.12@27573.78,11779.68 27618.95,11779.68 27635,11763.62 v1(27635,11741.62)
  Bottom Layer w11: C23.1@26654.06,11573.62 26654.06,11702.68 v1(26705,11753.62) 26731.05,11779.68 U13.37@26810,11779.68
  Bottom Layer w12: R163.1@26535,12732.28 26550.34,12747.62 26599,12747.62 26624.27,12722.35 26951.32,12722.35 27000,12673.67 27000,12622.33 27068.71,12553.62 27101,12553.62 27108.38,12561 27172.43,12561 v1(27172.72,12561.28) 27250.66,12561.28 27266.67,12545.27 v1(27266.67,12478.85)
  Bottom Layer w15: R158.1@26853.47,12107.04 26871.61,12088.9 v1(26871.61,12076.61) ; v1(27635,11741.62) 27668,11708.62 C6.1@27675,11708.62 ; R2.2@27706.14,11613.62 v1(27738,11613.62) ; R30.2@27706.14,11663.62 v1(27738,11663.62) ; R16.2@27706.14,11753.62 v1(27738,11753.62) ; R29.2@27706.14,11802.38 v1(27738,11802.38) ; R31.2@27706.14,11850.29 v1(27738,11850.29) ; R13.2@27706.14,11898.62 v1(27738,11898.62) ; R15.2@27706.14,11948.62 v1(27738,11948.62) ; v1(28454.43,13797.42) 28502.33,13845.31 P10.4@28502.33,13951.61
  Bottom Layer w20: C20.1@26449.54,13997.88 26449.54,14025.41 v1(26460.92,14036.78) U4.3@26460.92,14096.88 26460.92,14159.36 26483.12,14181.57 26603.56,14181.57 26634.12,14151.01 26634.12,14074.05 26668.55,14039.62 26762.98,14039.62 v1(26820.6,13982) C29.1@26856.27,13982 27119.55,13982 v1(27192.55,14055) 27344.7,14055 v1(27389.7,14010) 27463.72,13935.98 27573.17,13935.98 v1(27644.53,13864.62)
  other v1: 27585,12164 27510,12214 27510,12258 27594.53,13814.62 27644.53,13814.62
VDD_3V3C: C126.2 C127.1 C150.2 C151.1 C189.1 C190.2 C196.1 FB6.2 R37.1 R38.1 R40.1 R43.2 U1.16 U3.16 U11.44 U11.45 U11.46 U18.2 Y5.4 | length 6501.4
  Top Layer w10: U11.44@24881.53,13737.82 24881.53,13711.09 24889,13703.62 24904,13703.62 ; U11.45@24901.21,13737.82 24901.21,13706.41 24904,13703.62 ; U11.46@24920.9,13737.82 24920.9,13710.52 24914,13703.62 24904,13703.62
  Top Layer w12: v1(26855,13950) R37.1@26855,13983.86 ; U1.16@27079.41,13198.42 27148.8,13198.42 v1(27179.65,13229.26) ; v1(27261.14,13980.57) R40.1@27261.14,14010 ; U3.16@27562.07,13198.42 27623.58,13198.42 v1(27630,13192)
  Top Layer w15: Y5.4@24579,13452.48 v1(24579,13493.62) ; 24904,13703.62 24904,13668.62 24974.79,13597.83 C189.1@24974.79,13542.83 24990,13527.62 C190.2@24990,13480.57
  Top Layer w20: v3(25888.82,13249.71) 25888.82,13325.25 C196.1@25935.12,13371.56 ; v3(25997.2,13249.71) v3@25997.31,13249.6
  ART03 w30: v3(25942.31,13249.71) 25942.31,13571.76 26255.12,13884.57 26255.12,13938.57 26486.12,14169.57 27131.12,14169.57 27261.14,14039.56 v1(27261.14,13980.57) 26885.57,13980.57 v1(26855,13950) 26986.12,13818.88 26986.12,13539.57 27075.12,13450.57 27152.12,13450.57 27179.65,13423.05 v1(27179.65,13229.26)
  ART04 w12: v1(27152.29,12017.67) 27179.61,12017.67 27333.57,12171.62 27385.62,12171.62 27505,12291 27505,12500 27565,12560 27565,12816 27760,13011 v1(27760,13182)
  Bottom Layer w12: v1(27152.29,12017.67) 27152.29,12068.88 R38.1@27157,12073.59 ; C126.2@27201.62,13280.57 27201.62,13251.23 v1(27179.65,13229.26) 27179.65,13200.65 C127.1@27176,13197 27176,13173.7 27217.3,13132.4 27570.4,13132.4 v1(27630,13192) C151.1@27657,13192 27667,13182 C150.2@27717,13182 v1(27760,13182)
  Bottom Layer w15: R43.2@24579,13434.76 v1(24579,13493.62)
  other v1: 24982.12,13384.57 25030.12,13384.57 24981.12,13427.57 25028.12,13427.57
  other v3: 26028.06,13305.12 24636.76,13853.11 24663.94,13894.11
VDD_3V3D: C202.1 C204.2 FB12.1 FB13.1 R161.1 U20.3 | length 149
  Top Layer w20: 24992.89,12563 U20.3@25058,12563 U20.3@25088,12563
  Bottom Layer w15: v1(24980,12510) R161.1@25033.86,12510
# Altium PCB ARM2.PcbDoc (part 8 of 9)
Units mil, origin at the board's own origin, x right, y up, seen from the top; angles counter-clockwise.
Board outline 4700.79 x 3937.01 mil, 6 copper layers (Top Layer, GND02, ART03, ART04, PWR05, Bottom Layer); 689 components, 508 nets, 2312 pads, 1231 vias.

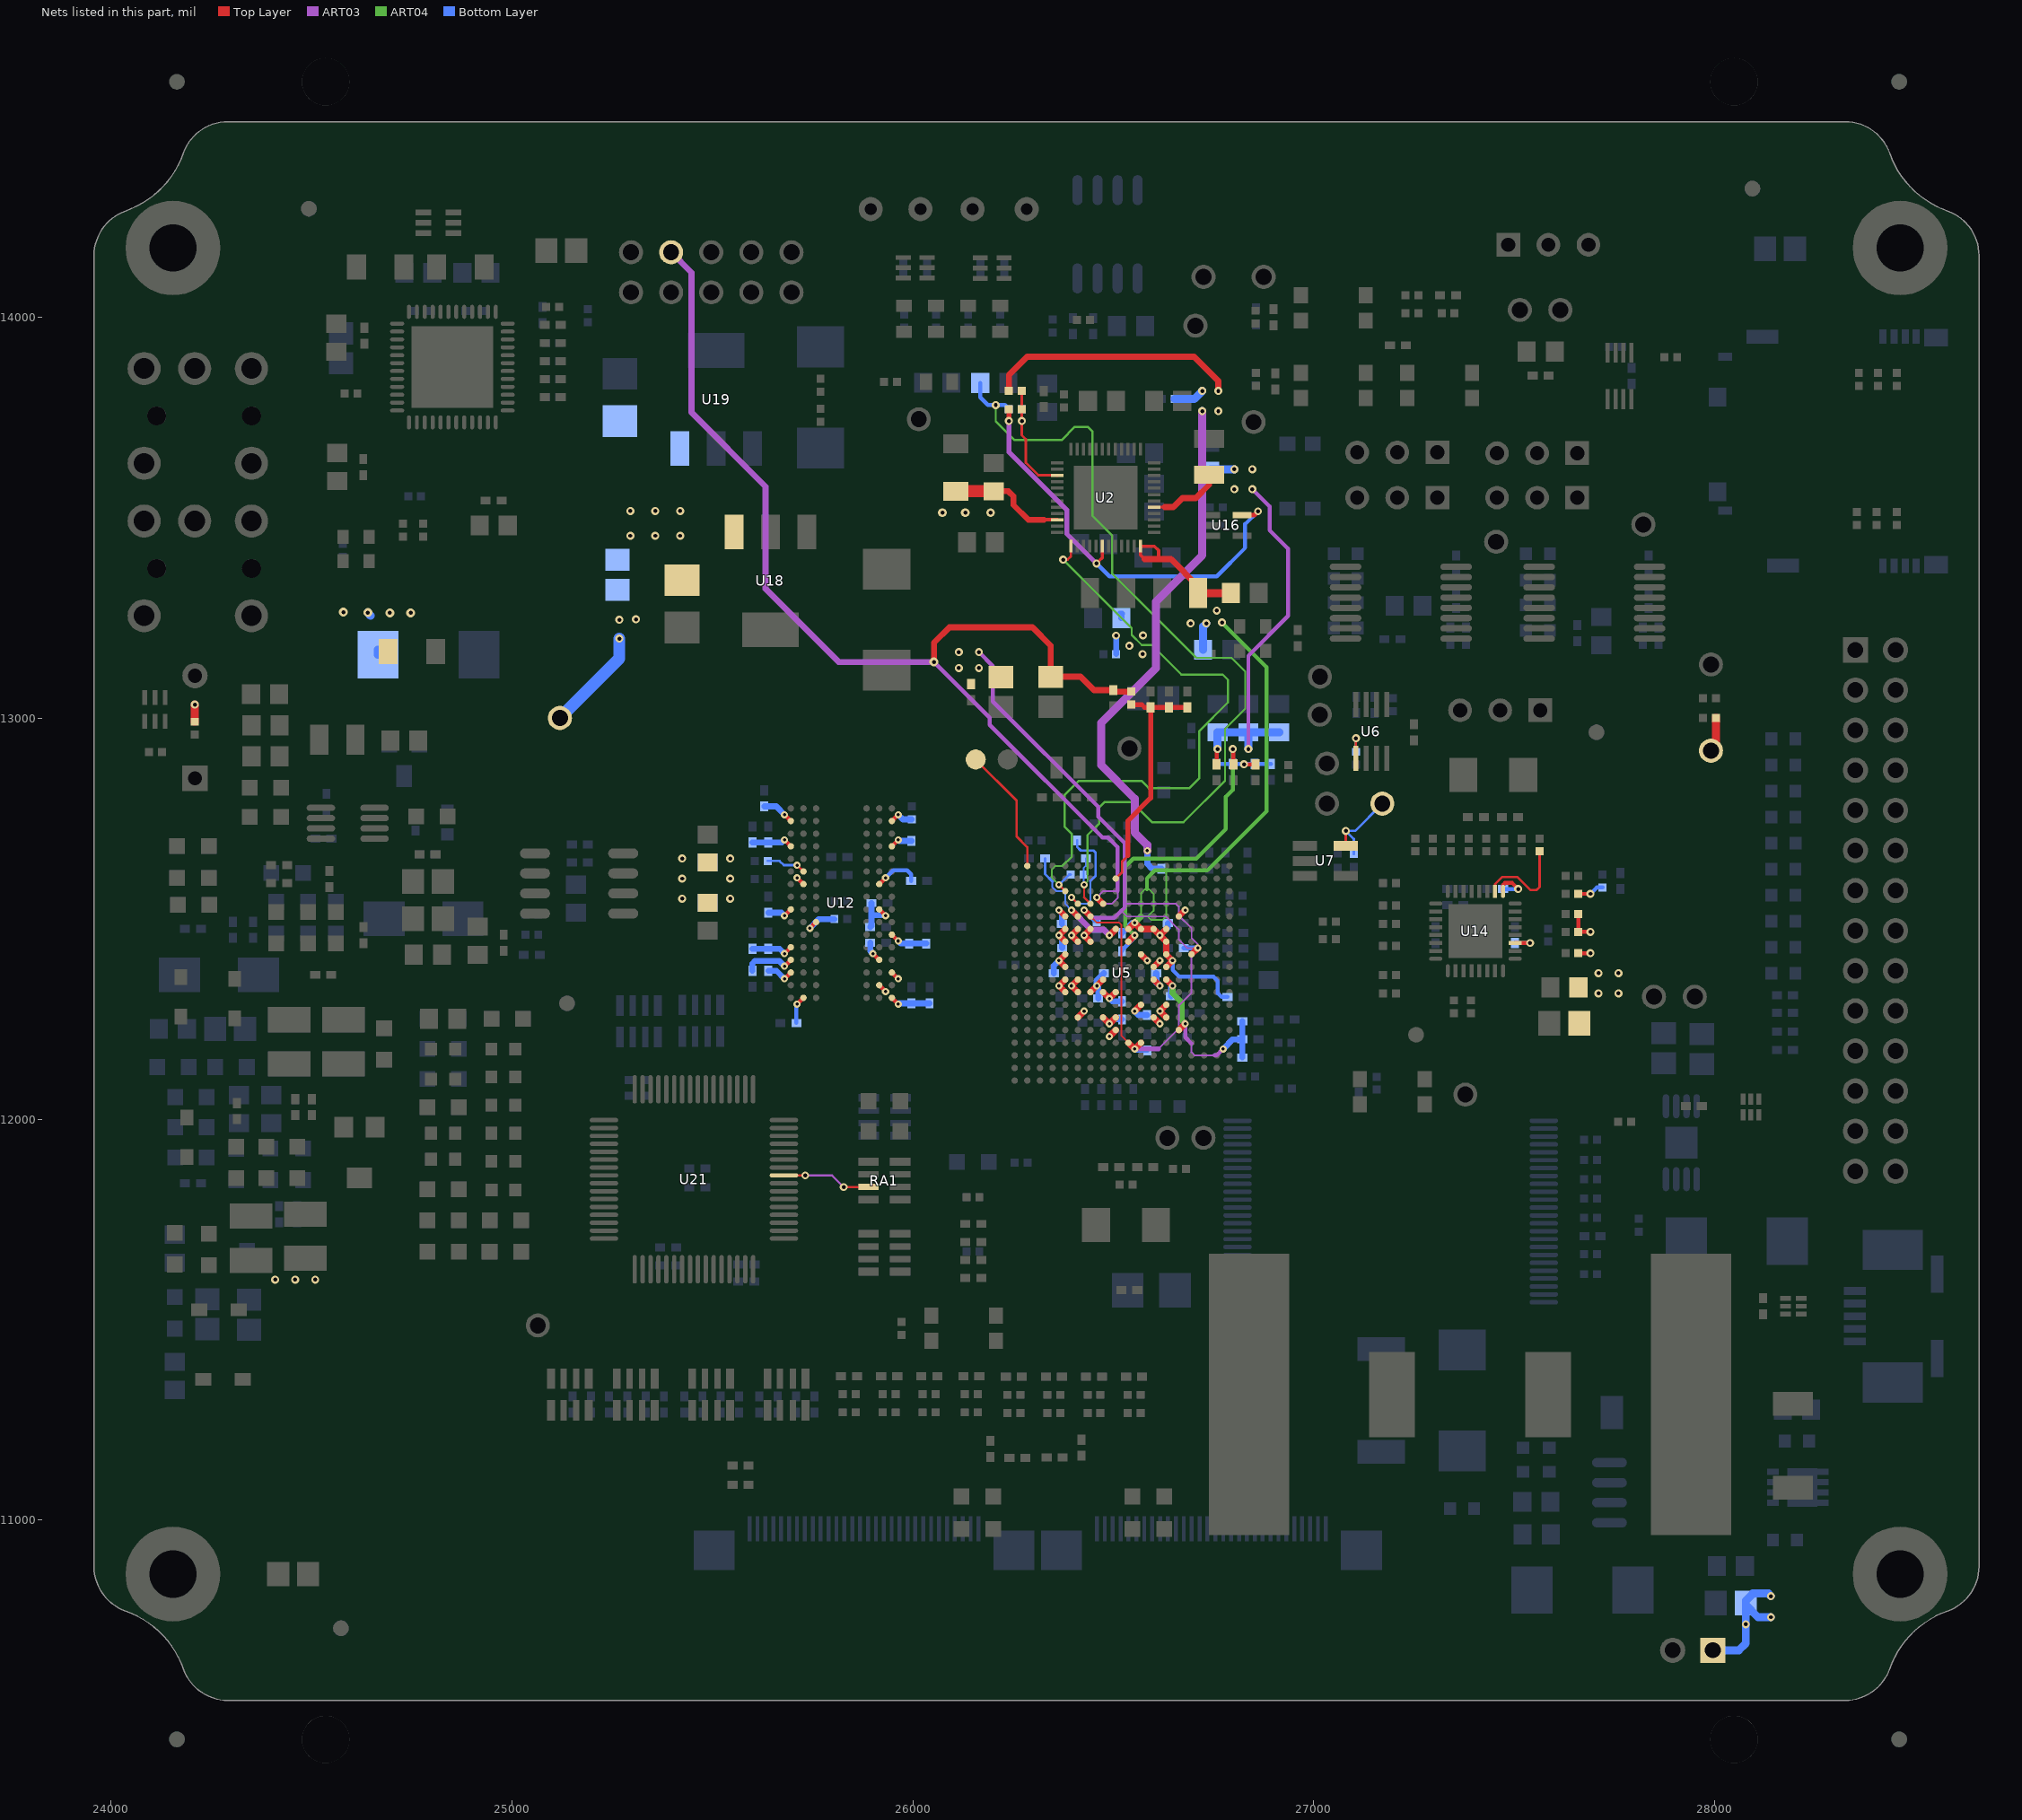
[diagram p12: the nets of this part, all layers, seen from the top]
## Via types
v1: diameter 20, hole 10, Top Layer to Bottom Layer, tented both sides, 870 vias
v2: diameter 18, hole 8, Top Layer to Bottom Layer, tented both sides, 273 vias
v3: diameter 22, hole 10, Top Layer to Bottom Layer, tented both sides, 64 vias
v4: diameter 20, hole 10, Top Layer to Bottom Layer, 18 vias
v5: diameter 22, hole 12, Top Layer to Bottom Layer, 4 vias
v6: diameter 22, hole 10, Top Layer to Bottom Layer, 1 vias
v7: diameter 39.37, hole 19.68, Top Layer to Bottom Layer, tented both sides, 1 vias

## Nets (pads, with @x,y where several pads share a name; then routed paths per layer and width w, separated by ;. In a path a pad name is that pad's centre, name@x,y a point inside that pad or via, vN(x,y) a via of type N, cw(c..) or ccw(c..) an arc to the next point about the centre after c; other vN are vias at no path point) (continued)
VDD_5V: C2.2 FB5.2 R239.2 TP11.1 U2.10 | length 554.4
  Top Layer w9: 26327,13494.88 U2.10@26359.99,13494.88
  Top Layer w15: C2.2@26202,13566 26238.7,13566 26251.28,13553.42 26251.28,13531.72 26288.12,13494.88 26327,13494.88
  Top Layer w30: R239.2@26107,13566 C2.2@26202,13566
  Bottom Layer w30: TP11.1@25120.12,13000.57 25268.2,13148.65 v1(25268.2,13198.47)
  other v1: 25268.2,13245.47 25309.62,13246.6
  other v3: 26074.12,13512.57 26131.12,13512.57 26194.12,13512.57
VDD_5V0: C5.1 C195.1 C197.1 FB5.1 FB17.1 P9.1 R32.1 R241.1 U18.3 U19.3 | length 410.1
  Top Layer w20: R32.1@24210,12991.14 v1(24210,13034)
  Bottom Layer w20: v3(24641.12,13263.57) 24641.12,13262.57 v3@24648.12,13255.57 ; C5.1@24666.46,13158.59 C5.1@24666.46,13170.91 ; P9.1@27995.12,10675.57 28060.12,10675.57 28077.4,10692.85 v1(28077.4,10740.57) FB17.1@28077.4,10788.37 ; v1(28140.12,10758.07) 28107.69,10758.07 FB17.1@28077.4,10788.37 ; v1(28140.12,10810.57) 28133.6,10817.1 28095.14,10817.1 28077.4,10799.35 FB17.1@28077.4,10793.62 FB17.1@28077.4,10788.37
  other v1: 24410,11600 24460,11600 24510,11600 25296,13455 25358,13455 25420,13455 25296,13517 25358,13517 25420,13517
  other v3: 24696.12,13262.57 24748.12,13262.57 24580.12,13264.57
VDD_ADC: C93.1 FB2.1 R27.1 TP29.1 U5.D8 | length 3049.4
  Top Layer w15: v3(26052.84,13140.15) 26052.84,13188.14 26091.48,13226.78 26298.38,13226.78 26344,13181.16 FB2.1@26344,13103.4 ; FB2.1@26327.07,13103.4 FB2.1@26344,13103.4 ; v2(26458.99,12552.98) U5.D8@26474.74,12537.23 ; R27.1@26545,13066.14 26503.86,13066.14 C93.1@26500,13070 26452,13070 26418.6,13103.4 FB2.1@26344,13103.4
  ART03 w4.4: 26511.12,12569.35 26511.12,12568.97 ; 26511.12,12568.97 26511.12,12551.7 26496.9,12537.48 26474.49,12537.48 v2(26458.99,12552.98) 26474.98,12568.97 26511.12,12568.97
  ART03 w10: v3(26052.84,13140.15) 26192.12,13000.87 26192.12,12983.57 26473.12,12702.57 26487.04,12702.57 26511.12,12678.49 26511.12,12569.35
  ART03 w15: TP29.1@25397.5,14162 25448.12,14111.38 25448.12,13762.57 25633.12,13577.57 25633.12,13322.57 25815.54,13140.15 v3(26052.84,13140.15)
VDD_CORE: C11.2 C39.2 C40.2 C41.1 C42.1 C43.1 C44.1 C45.1 C46.1 C47.1 C48.1 C49.1 C50.1 C51.1 C52.1 C53.1 C54.1 C55.2 L3.2 U2.29 U5.F6 U5.F7 U5.G6 U5.G7 U5.G10 U5.H11 U5.J12 U5.K6 U5.K8 U5.K12 U5.L6 U5.L7 U5.L8 U5.L9 U5.M11 U5.M13 U5.N8 U5.N9 U5.N12 U5.N13 | length 2852.3
  Top Layer w7: U2.29@26602.12,13526.38 26628,13526.38
  Top Layer w10: C53.1@26758.02,12885 26758.02,12921.02 v1(26760,12923) ; v1(26798,12923) 26800,12921 C48.1@26800,12885 ; v1(26826,12885) C54.1@26855,12885
  Top Layer w15: 26628,13526.38 26649.75,13526.38 26672.44,13549.07 26706.07,13549.07 26739,13582
  Top Layer w16: U5.L6@26411.74,12316.76 v2(26395.99,12332.51) U5.K6@26411.74,12348.25 ; U5.G6@26411.74,12442.74 v2(26395.99,12458.49) U5.F6@26411.74,12474.24 ; U5.L7@26443.24,12316.76 v2(26458.99,12332.51) U5.K8@26474.74,12348.25 ; U5.G7@26443.24,12442.74 v2(26427.49,12458.49) U5.F7@26443.24,12474.24 ; U5.N8@26474.74,12253.76 v2(26490.48,12238.02) U5.N9@26506.23,12253.76 ; U5.L8@26474.74,12316.76 v2(26490.48,12301.02) U5.L9@26506.23,12316.76 ; U5.G10@26537.73,12442.74 v2(26553.48,12458.49) ; v2(26553.47,12269.52) U5.M11@26569.22,12285.26 ; U5.H11@26569.22,12411.24 v2(26584.97,12395.5) ; U5.N12@26600.72,12253.76 v2(26616.47,12238.02) ; U5.K12@26600.72,12348.25 v2(26616.47,12332.51) ; U5.J12@26600.72,12379.75 v2(26616.47,12395.5) ; U5.N13@26632.22,12253.76 v2(26616.47,12269.52) U5.M13@26632.22,12285.26
  ART03 w10: v1(26837,12923) 26837,13155.79 26936.12,13254.91 26936.12,13422.57 26890.12,13468.57 26890.12,13527.88 v1(26847,13571)
  ART04 w10: v2(26553.48,12458.49) 26530.12,12481.84 26530.12,12629.57 26550.2,12649.65 26707.2,12649.65 26781,12723.45 26781,12804.04 26798,12821.04 v1(26798,12923)
  Bottom Layer w10: C47.1@26521.98,12419 26521.98,12421.37 26553.48,12452.87 v2(26553.48,12458.49) ; C45.1@26758.02,12886 C46.1@26798.02,12886 ; v1@26798.02,12920.98 C46.1@26798.02,12886 ; v1@26825,12885 26824,12886 C46.1@26798.02,12886 ; v1(26826,12885) 26827,12886 C41.1@26853.02,12886 C42.1@26893.02,12886
  Bottom Layer w15: v2(26458.99,12332.51) 26462.48,12329.02 C44.1@26462.48,12301.02 ; v2(26490.48,12238.02) 26501.47,12249 C52.1@26521.98,12249 ; v2(26490.48,12301.02) 26497.5,12294 C50.1@26521.98,12294
  Bottom Layer w16: v2(26458.99,12332.51) 26458.99,12346.02 C43.1@26476.98,12364 ; v2(26553.47,12269.52) 26562.99,12260 C51.1@26584,12260 ; C49.1@26606.98,12364 26606.98,12341.99 v2(26616.47,12332.51)
  Bottom Layer w20: C11.2@26739,13617 26743,13621 v1(26802,13621) ; v1(26760,12923) C40.2@26760,12965 C55.2@26837,12965 ; v1(26837,12923) C55.2@26837,12965 ; C39.2@26914,12965 C55.2@26837,12965
  other v1: 26802,13571 26847,13621
VDD_MPU: C12.2 C62.2 C63.1 C64.1 C65.1 L2.2 U2.24 U5.F10 U5.F11 U5.F12 U5.F13 U5.G13 U5.H13 U5.J13 | length 2223.9
  Top Layer w8: 26578.12,13396.57 26567.67,13407.03 U2.24@26567.67,13428.94 26602.76,13428.94 26613.12,13418.57 26613.12,13396.57
  Top Layer w15: 26578.12,13396.57 26613.12,13396.57 26644.12,13396.57 26712.06,13328.64 L2.2@26712.06,13312 L2.2@26713,13312.94
  Top Layer w16: U5.F10@26537.73,12474.24 v2(26553.48,12489.99) U5.F11@26569.22,12474.24 U5.F12@26600.72,12474.24 v2(26616.47,12458.49) ; U5.J13@26632.22,12379.75 v2(26647.97,12395.5) U5.H13@26632.22,12411.24 U5.G13@26632.22,12442.74 v2(26616.47,12458.49) ; U5.F13@26632.22,12474.24 v2(26616.47,12458.49)
  Top Layer w20: L2.2@26712.06,13312 C12.2@26793,13312
  ART04 w4.4: 26632.06,12620.57 26632.06,12505.61 26623.06,12496.61 26595.21,12496.61 26586.19,12505.64 ; 26586.19,12505.64 26600.47,12519.91 26600.47,12562.23 26589.12,12573.57 26584.12,12573.57 26579.12,12573.57 26569.12,12563.57 26569.12,12505.64 26586.19,12505.64
  ART04 w10: 26584.12,12573.57 26584.12,12600.67 26604.02,12620.57 26632.06,12620.57 26735.12,12620.57 26882.44,12767.88 26882.44,13127.26 v1(26771.12,13238.57)
  ART04 w15: v2(26553.48,12489.99) 26569.12,12505.64
  Bottom Layer w10: v2(26647.97,12395.5) 26647.97,12372.03 26665,12355 26750,12355 26760.75,12344.25 26760.75,12314.25 26770,12305 C63.1@26785,12305
  Bottom Layer w15: C64.1@26521.98,12464 26547.97,12489.99 v2(26553.48,12489.99) ; v2(26616.47,12458.49) 26635.96,12477.98 C65.1@26635.96,12489
  Bottom Layer w20: C62.2@26724.06,13170.61 26724.06,13228.51 v1(26732.12,13236.57)
  other v1: 26693.12,13236.57 26758.12,13268.57
VDD_MPUON: TP2.1 U5.A2 | length 318.6
  Top Layer w6: TP2.1@26157,12897 26259,12795 26259,12705 26285.76,12678.24 U5.A2@26285.76,12631.72
VDD_PHYA: C131.1 C132.1 C133.2 FB4.2 R120.2 R121.2 R122.2 R123.2 R137.2 U14.1 U14.27 | length 346.6
  Top Layer w10: U14.1@27472.06,12568 27472.06,12584.06 27477,12589 27495,12589 v1(27510,12574) ; U14.27@27502.11,12439.45 v1(27539.55,12439.45) ; R123.2@27660,12414 v1(27690,12414) ; R121.2@27660,12512 R122.2@27660,12467 v1(27690,12467) ; R120.2@27660,12562 v1(27690,12562)
  Bottom Layer w10: C131.1@27472.06,12574 v1(27510,12574) ; C132.1@27502.11,12439.45 v1(27539.55,12439.45) ; v1(27690,12562) 27705.86,12577.86 R137.2@27720,12577.86
  other v1: 27710,12314 27760,12314 27710,12364 27760,12364
VDD_PLL: C79.1 C92.1 C94.1 C106.1 FB1.2 U5.E7 U5.H15 U5.R10 U5.R11 | length 2350.1
  Top Layer w4.4: U5.E7@26443.24,12505.73 26458.98,12489.99 26515.14,12489.99 26520.73,12484.39 26520.73,12207.77 U5.R10@26537.73,12190.77
  Top Layer w16: v2(26427.49,12521.48) U5.E7@26443.24,12505.73 ; U5.R10@26537.73,12190.77 v2(26553.48,12175.03) U5.R11@26569.22,12190.77 ; U5.H15@26695.21,12411.24 v2(26710.96,12426.99)
  ART03 w4.4: 26520,12519.5 26534.01,12505.49 26631.21,12505.49 26663.46,12473.24 26663.46,12448.24 26684.71,12426.99 v2(26710.96,12426.99) ; 26529.12,12536.98 26656.72,12536.98 26663.47,12530.23 26663.47,12508.23 26695.46,12476.24 26695.46,12452.07 26710.96,12436.57 v2(26710.96,12426.99) ; 26612.27,12175.03 26663.96,12226.71 26663.96,12284.4 26694.96,12315.4 26694.96,12410.99 v2(26710.96,12426.99)
  ART03 w10: v1(26165,13165) 26200.04,13129.96 26200.04,13041.66 26463.12,12778.57 26463.12,12753.82 26529.12,12687.82 26529.12,12536.98 26529.12,12528.63 26520,12519.5 26502.11,12501.61 26447.36,12501.61 v2(26427.49,12521.48)
  ART03 w12: v2(26553.48,12175.03) 26612.27,12175.03
  Bottom Layer w12: v2(26427.49,12521.48) 26453.49,12495.48 C94.1@26458.99,12495.48 ; v2(26553.48,12175.03) 26556.98,12171.53 C79.1@26584.97,12171.53 ; C92.1@26675.96,12426.99 v2(26710.96,12426.99)
  other v1: 26115,13125 26165,13125 26115,13165
VDD_RTC: C104.1 U5.D6 | length 272
  Top Layer w6: v2(26395.99,12552.98) U5.D6@26411.74,12537.23
  Bottom Layer w4.4: v2(26395.99,12552.98) 26411.49,12537.48 26435.48,12537.48 26442.99,12544.99 26442.99,12593.99
  Bottom Layer w6: C104.1@26410,12695 26410,12679 26419,12670 26451,12670 26455.99,12665.01 26455.99,12606.99 26442.99,12593.99
VDDS: C80.1 C81.1 C82.1 C83.1 C84.1 C85.1 R8.2 R9.1 U5.E6 U5.E14 U5.F9 U5.K13 U5.N6 U5.P9 U5.P14 | length 2944.6
  Top Layer w15: R8.2@26239.72,13816 26239.72,13855.98 26285.36,13901.62 26701.38,13901.62 26762,13841 v1(26762,13816)
  Top Layer w16: v2(26395.99,12521.48) U5.E6@26411.74,12505.73 ; U5.N6@26411.74,12253.76 v2(26427.49,12269.51) ; v2(26490.48,12206.53) U5.P9@26506.23,12222.27 ; v2(26490.48,12458.5) U5.F9@26506.23,12474.24 ; U5.K13@26632.22,12348.25 v2(26647.97,12332.51) ; U5.P14@26663.71,12222.27 v2(26679.46,12238.02) ; U5.E14@26663.71,12505.73 v2(26679.46,12521.48)
  ART03 w4.4: 26694.96,12188.79 26694.96,12167.04 26702.96,12159.04 26752.58,12159.04
  ART03 w10: v2(26679.46,12238.02) 26679.46,12204.29 26694.96,12188.79 ; 26752.58,12159.28 26758.2,12159.28 v2(26773.95,12175.03)
  ART03 w15: v2(26395.99,12521.48) 26444.9,12472.57 26476.41,12472.57 v2(26490.48,12458.5)
  ART03 w20: v2(26585.12,12669.82) 26585.12,12683.57 26553.51,12715.19 26553.51,12799.19 26469.51,12883.19 26469.51,12988.09 26606.61,13125.19 26606.61,13291.06 26722,13406.45 v1(26722,13766)
  ART04 w15: v2(26647.97,12332.51) 26647.97,12314.03 26670.8,12291.2 26670.8,12246.67 v2(26679.46,12238.02)
  Bottom Layer w4.4: 26348.14,12591.86 26348.48,12591.52 26348.48,12578.57 26358.08,12568.97 26372.97,12568.97 ; 26373,12569 26379.98,12562.02 26379.98,12537.49 v2(26395.99,12521.48)
  Bottom Layer w7: C81.1@26330,12650 26330,12611.24 26348.76,12592.48
  Bottom Layer w15: v2(26585.12,12669.82) 26585.12,12636.59 26596.72,12625 C82.1@26620,12625 ; C85.1@26644,12307 26644,12328.54 v2(26647.97,12332.51) ; v2(26773.95,12175.03) 26797.92,12199 C84.1@26822,12199 ; C83.1@26822,12154 C84.1@26822,12199 ; 26822,12174 C84.1@26822,12199 ; C80.1@26822,12244 C84.1@26822,12199
  Bottom Layer w20: R9.1@26653.14,13796 26702,13796 v1(26722,13816)
  other v1: 26762,13766
VDDS_DDR: C9.2 C95.2 C96.2 C97.1 C98.1 C99.1 C100.1 C101.1 C102.1 C103.1 C107.1 C108.1 C109.1 C110.1 C111.1 C112.1 C113.1 C114.1 C115.1 C116.1 C117.1 C118.2 C119.1 C120.1 C121.1 C122.2 R6.2 R97.1 R98.1 U5.E5 U5.F5 U5.G5 U5.H5 U5.J5 U5.K5 U5.L5 U12.A1 U12.A8 U12.B2 U12.C1 U12.C9 U12.D2 U12.D9 U12.E9 U12.F1 U12.G7 U12.H2 U12.H9 U12.K2 U12.K8 U12.N1 U12.N9 U12.R1 U12.R9 | length 1727.1
  Top Layer w10: v2(25680.27,12350) U12.C9@25696.02,12365.74 ; v2(25680.27,12381.5) U12.D9@25696.02,12397.24 ; v2(25680.27,12412.99) U12.E9@25696.02,12428.73 ; v2(25680.27,12507.48) U12.H9@25696.02,12523.22 ; v2(25680.27,12696.45) U12.N9@25696.02,12680.7 ; v2(25680.27,12759.44) U12.R9@25696.02,12743.69 ; v2(25711.77,12287.01) U12.A8@25727.51,12302.75 ; v2(25711.77,12601.96) U12.K8@25727.51,12586.21 ; v2(25743.27,12475.99) U12.G7@25759.01,12491.73 ; v2(25900.74,12412.99) U12.D2@25916.49,12397.24 ; U12.B2@25916.49,12334.25 v2(25932.23,12318.51) ; U12.H2@25916.49,12523.22 v2(25932.23,12507.48) ; U12.K2@25916.49,12586.21 v2(25932.23,12601.96) ; U12.A1@25947.98,12302.75 v2(25963.73,12287.01) ; U12.C1@25947.98,12365.74 v2(25963.73,12350) ; U12.F1@25947.98,12460.23 v2(25963.73,12444.49) ; U12.N1@25947.98,12680.7 v2(25963.73,12696.45) ; U12.R1@25947.98,12743.69 v2(25963.73,12759.44)
  Top Layer w16: v2(26364.5,12521.48) U5.E5@26380.25,12505.73 ; U5.L5@26380.25,12316.76 v2(26364.5,12332.51) U5.K5@26380.25,12348.25 ; U5.J5@26380.25,12379.75 v2(26364.5,12395.5) U5.H5@26380.25,12411.24 ; U5.G5@26380.25,12442.74 v2(26364.5,12458.49) U5.F5@26380.25,12474.24
  Bottom Layer w10: C107.1@25710,12240 25710,12285.24 v2(25711.77,12287.01) ; v2(25932.23,12601.96) 25951.27,12621 25986,12621 25996,12611 C112.1@25996,12594
  Bottom Layer w15: C98.1@25600,12370 25600,12388 25607,12395 25666.77,12395 v2(25680.27,12381.5) ; C102.1@25600,12425 C116.1@25640,12425 25668.26,12425 v2(25680.27,12412.99) ; C97.1@25600,12690 C113.1@25640,12690 ; C113.1@25630,12690 C113.1@25640,12690 ; C119.1@25630,12780 25659.71,12780 v2(25680.27,12759.44) ; C120.1@25640,12370 25660.27,12370 v2(25680.27,12350) ; C108.1@25640,12515 25672.75,12515 v2(25680.27,12507.48) ; v2(25680.27,12696.45) 25673.83,12690 C113.1@25640,12690 ; v2(25743.27,12475.99) 25766.25,12498.97 R98.1@25804.72,12498.97 ; C101.1@25894,12440 25894,12419.73 v2(25900.74,12412.99) ; C114.1@25894,12479 25897,12482 25897,12509 ; C117.1@25897,12539 25897,12509 ; v2(25932.23,12507.48) 25930.71,12509 25897,12509 ; v2(25963.73,12287.01) 25965.72,12289 C109.1@25997,12289 C115.1@26042,12289 ; v2(25963.73,12444.49) 25970.21,12438 C121.1@25991.08,12438 C111.1@26034,12438 ; v2(25963.73,12696.45) 25966.17,12694 C110.1@25997,12694 ; v2(25963.73,12759.44) 25975.31,12747.86 R97.1@25997.23,12747.86 ; C103.1@26351.98,12364 26351.98,12382.97 v2(26364.5,12395.5) ; v2(26364.5,12458.49) 26372.49,12450.5 C99.1@26372.49,12426.99 ; v2(26364.5,12521.48) 26372,12513.98 C100.1@26372,12487 ; v1(26507,13206) 26507.41,13205.59 R6.2@26507.41,13160 ; C9.2@26517,13261 C9.2@26520.12,13261 ; C9.2@26520.12,13249.6 C9.2@26520.12,13261 ; C9.2@26522,13261 C9.2@26520.12,13261
  other v1: 25425,12550 25545,12550 25425,12600 25545,12600 25425,12650 25545,12650 26573.12,13160 26540.12,13180.57 26574.12,13206.57
VIO: R7.2 U2.18 U16.5 | length 1079.8
  Top Layer w8: v1@26463.64,13391.46 26473.19,13401 U2.18@26473.19,13428.94
  Top Layer w12: v1(26239.72,13741) R7.2@26239.72,13771 ; U16.5@26821.37,13506.59 26851.59,13506.59 v1(26861,13516)
  ART03 w12: v1(26239.72,13741) 26239.72,13663.98 26384.12,13519.57 26384.12,13460.06 v1(26458.19,13386)
  Bottom Layer w10: v1@26457.1,13386 v1(26458.19,13386) 26490.61,13353.57 26757.86,13353.57 26829.12,13424.84 26829.12,13484.12 v1(26861,13516)
VLDO1: R5.1 R7.1 R8.1 U2.3 | length 304.3
  Top Layer w6: R8.1@26272,13816 R7.1@26272,13771 v1(26272,13741) 26272,13706 26282,13696 26282,13637 26313,13606 26359.12,13606 U2.3@26359.99,13605.12
  Bottom Layer w6: v1(26272,13741) R5.1@26272,13771
VREFP_ADC: C31.1 C32.1 C33.1 R27.2 U5.B9 | length 605.8
  Top Layer w6: U5.B9@26506.23,12600.22 26521.98,12615.97 26521.98,12642.6 26536.67,12657.29
  Top Layer w12: 26536.67,12657.29 26536.67,12744.39 26593.5,12801.22 C32.1@26593.5,13027 ; R27.2@26545,13033.86 26571.14,13033.86 26578,13027 C32.1@26593.5,13027 ; C31.1@26685,13027 C33.1@26639.25,13027 C32.1@26593.5,13027
VRTC: C16.1 C105.1 R5.2 R26.1 U5.D7 | length 2251.4
  Top Layer w4.4: 26427.49,12552.98 v2(26427.49,12584.47)
  Top Layer w6: 26427.49,12552.98 U5.D7@26443.24,12537.23
  ART04 w4.4: v2(26427.49,12584.47) 26435.81,12592.79 26435.81,12610.62
  ART04 w5.5: v1(26207,13781) 26207,13740.7 26254.12,13693.57 26371.24,13693.57 26404.26,13726.6 26436.81,13726.6 26448.42,13714.98 26448.42,13504.49 26497.12,13455.78 26497.12,13360.57 26707.12,13150.57 26795.12,13150.57 26829.12,13116.57 26829.12,13023.57 26778.77,12973.22 26778.77,12844.03 26675.41,12740.67 26596.69,12740.67 26546.79,12790.57 26478.12,12790.57 26465.12,12777.57 26465.12,12737.57 26435.81,12708.26 26435.81,12610.62
  Bottom Layer w4.4: v2@26426.14,12585.82 R26.1@26426.14,12610 26426.14,12626.14 26431.74,12631.74 C105.1@26431.74,12650
  Bottom Layer w10: C16.1@26168.4,13836 26168.4,13800.27 26187.67,13781 v1(26207,13781) 26229.72,13781 R5.2@26239.72,13771
VSYNCH: RA1.7 U21.41 | length 222.9
  Top Layer w6: U21.41@25678.78,11859.84 v1(25731.98,11859.84) ; v1(25827.75,11830.75) RA1.7@25889.63,11830.75
  ART03 w5.5: v1(25731.98,11859.84) 25798.67,11859.84 v1(25827.75,11830.75)
WAKEUP: R26.2 U2.13 U5.C5 | length 1556.7
  Top Layer w6: v2(26364.5,12584.47) U5.C5@26380.25,12568.72 ; 26386.33,13395.45 26394.44,13403.57 U2.13@26394.44,13428.94
  ART04 w4.4: v2(26364.5,12584.47) 26347,12601.97 26347,12623 26355.47,12631.47 26373,12631.47
  ART04 w5.5: 26373,12631.47 26396.82,12655.29 26396.82,12711.18 26379.12,12728.88 26379.12,12809.3 26413.7,12843.88 26570.52,12843.88 26588.46,12825.94 26690.11,12825.94 26714.05,12849.88 26714.05,12967.5 26786.12,13039.57 26786.12,13095.57 26773.12,13108.57 26670.12,13108.57 26596.12,13182.57 26571.12,13182.57 26546.04,13207.66 26546.04,13224.32 v1(26374.91,13395.45)
  Bottom Layer w6: v2(26364.5,12584.47) 26390.04,12610 R26.2@26393.86,12610
WP: R156.2 TP4.1 U7.5 | length 222.8
  Top Layer w6: U7.5@27080,12681.5 v1(27080,12719)
  Bottom Layer w6: R156.2@27100,12661.14 27100,12699 v1(27080,12719) 27103,12719 TP4.1@27171,12787
XDMA_EVENT_INTR0: R18.2 U6.1 | length 83.9
  Top Layer w6: U6.1@27105.2,12900 v1(27105.2,12950)
  Bottom Layer w6: R18.2@27105.2,12916.14 v1(27105.2,12950)
YEL_C: R130.2 TP39.1 | length 86.5
  Top Layer w20: TP39.1@27990.56,12918.96 28003.03,12931.43 R130.2@28003.03,13000.26
YELA: R135.1 U14.2 | length 241.9
  Top Layer w6: U14.2@27452.36,12568 27452.36,12586.36 27470,12604 27507.62,12604 27540,12571.62 27556,12571.62 27563.11,12578.73 R135.1@27563.11,12667.86
ZQ: R99.2 U12.L8 | length 100.2
  Top Layer w6: v2(25711.77,12633.46) U12.L8@25727.51,12617.71
  Bottom Layer w6: R99.2@25638.14,12643.97 25668,12643.97 25678.51,12633.46 v2(25711.77,12633.46)
pads on no net: 1.1 2.1 3.1 "J2. " ?.1 Designator303.0 Designator303.1 Designator316.0 Designator316.1 P6.24 P16. P16.3 P16.5 P17. P17.3 P17.5 Q3.3 Q3.4 Q3.5 RA1.1 RA1.4 RA1.5 RA1.8 RA6.4 RA6.5 RA11.3 RA11.4 RA11.5 RA11.6 Radj1.1 U2.14 U2.15 U2.16 U2.17 U2.33 U2.34 U2.35 U2.36 U2.37 U2.38 U2.44 U5.F16 U5.M5 U5.M15 U5.P18 U9.3 U9.5 U10.5 U11.7 U11.8 U11.9 U11.10 U11.12 U11.19 U11.22 U11.27 U11.28 U11.29 U11.30 U11.31 U11.32 U11.34 U11.35 U11.47 U11.48 U12.J1 U12.J9 U12.L1 U12.L9 U13.1 U13.2 U13.3 U13.4 U13.5 U13.11 U13.14 U13.15 U13.20 U13.21 U13.22 U13.23 U13.24 U13.25 U13.26 U13.27 U13.28 U13.33 U13.34 U13.35 U13.38 U13.39 U13.40 U13.45 U13.46 U13.47 U13.48 U16.1 U18.4 U19.4
copper on no net:
  other v1: 28183.43,13773.79

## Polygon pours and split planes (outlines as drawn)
NetC241_1 on Top Layer "Top Layer-No Net" (solid, remove dead copper, pour order 1005): 24584,13011 24712.67,13011 24727,12996.67 24727,12869.55 24719.45,12862 24582,12862 24576,12868 24576,13003
DGND on Top Layer "Top Layer-No Net" (solid, remove dead copper, pour order 1001): 24806.12,12435.57 25022.1,12435.57 25040.06,12417.61 25040.06,12352.61 25024.45,12337 24805,12337 24801,12341 24801,12430.45
DGND on Top Layer "Top Layer-No Net" (solid, remove dead copper, pour order 1009): 27460,14066.15 27546,14066.15 27552,14060.15 27552,13808.15 27541,13797.15 27482.53,13797.15 27456,13823.67 27456,14062.15
VDD_3V3D on Top Layer "Top Layer-No Net" (solid, remove dead copper, pour order 1000): 24805,12631 24986.3,12631 25005.49,12611.81 25005.49,12482.04 24987.45,12464 24803,12464 24796,12471 24796,12622
VCCD on Top Layer "TOP-No Net" (solid, remove dead copper, pour order 1000): 17 vertices, not listed, extent 24661.92,12552.03 24783.16,12679.54
VDD_3V3C on Top Layer "TOP-No Net" (solid, remove dead copper, pour order 1018): 22 vertices, not listed, extent 25620.12,13232.83 26051,13597.45
VDD_1V8B on Top Layer "TOP-No Net" (solid, remove dead copper, pour order 1017): 24640.65,13756.25 24655.59,13741.32 24655.59,13657.51 24632.65,13634.57 24456.12,13634.57 24445.12,13645.57 24445.12,13741.67 24459.7,13756.25
VDCDC1 on Top Layer "TOP-No Net" (solid, remove dead copper, pour order 1016): 26330.43,13359.53 26456.99,13359.53 26475.2,13341.31 26475.2,13249.64 26465.32,13239.76 26332.9,13239.76 26317.46,13255.19 26317.46,13346.56
VDD_CORE on Top Layer "TOP-No Net" (solid, remove dead copper, pour order 1015): 17 vertices, not listed, extent 26694.12,13551.57 26864.12,13643.57
VDD_MPU on Top Layer "TOP-No Net" (solid, remove dead copper, pour order 1014): 18 vertices, not listed, extent 26677.12,13221.57 26817.12,13371.57
VDD_5V on Top Layer "TOP-No Net" (solid, remove dead copper, pour order 1013): 26050.12,13595.57 26222.12,13595.57 26227.12,13590.57 26231.12,13586.57 26231.12,13579.57 26231.12,13508.57 26226.12,13503.57 26221.12,13498.57 26213.12,13498.57 26053.12,13498.57 26042.12,13509.57 26041.12,13510.57 26041.12,13557.57 26041.12,13586.57 26050.12,13595.57
AGND_AUD on Top Layer "TOP-No Net" (solid, remove dead copper, pour order 1012): 24496.12,13940.57 24593.68,13940.57 24602.63,13931.62 24604.12,13930.13 24604.12,13905.57 24604.12,13856.57 24602.12,13854.57 24595.12,13847.57 24587.12,13847.57 24496.12,13847.57 24487.12,13856.57 24485.12,13858.57 24485.12,13867.57 24485.12,13929.57 24496.12,13940.57
3V3_AUD on Top Layer "TOP-No Net" (solid, remove dead copper, pour order 1011): 18 vertices, not listed, extent 24487.12,13956.57 24600.12,14046.57
VDD_3V3C on Top Layer "TOP-No Net" (solid, remove dead copper, pour order 1010): 24968.12,13514.57 25043.12,13514.57 25052.12,13505.57 25052.12,13380.57 25042.12,13370.57 24976.12,13370.57 24963.12,13383.57 24963.12,13509.57
VDD_5V0 on Top Layer "TOP-No Net" (solid, remove dead copper, pour order 1009): 24583.14,13055.56 24563.12,13075.57 24563.12,13272.57 24578.11,13287.56 24740.35,13287.56 24759.35,13268.56 24759.35,13081.56 24733.35,13055.56
PWR_ARM on Top Layer "TOP-No Net" (solid, remove dead copper, pour order 1008): 24781.12,13040.57 24774.12,13047.57 24774.12,13268.57 24793.12,13287.57 24879.12,13287.57 24894.12,13272.57 24894.12,13049.57 24885.12,13040.57
DGND on Top Layer "Top Layer-No Net" (solid, remove dead copper, pour order 1006): 25733.12,13324.57 25818.12,13324.57 25827,13333.45 25827,13474.7 25805.12,13496.57 25744.12,13496.57 25724,13476.45 25724,13333.7
AGND_AUD on Top Layer "TOP-No Net" (solid, remove dead copper, pour order 1007): 25014.83,14239.11 25102.59,14239.11 25114.62,14227.07 25114.62,14105.07 25103.62,14094.07 25019.62,14094.07 25005.83,14107.87 25005.83,14230.11
DGND on Top Layer "TOP-No Net" (solid, remove dead copper, pour order 1006): 19 vertices, not listed, extent 25133.62,14093.07 25238.62,14241.07
DGND on Top Layer "TOP-No Net" (solid, remove dead copper, pour order 1005): 24867.12,13511.57 24939.12,13511.57 24945.12,13505.57 24945.12,13413.57 24937.12,13405.57 24870.12,13405.57 24860.12,13415.57 24860.12,13504.57
DGND on Top Layer "TOP-No Net" (solid, remove dead copper, pour order 1004): 17 vertices, not listed, extent 24493.12,13531.57 24681.12,13621.57
NetD6_1 on Top Layer "TOP-No Net" (solid, remove dead copper, pour order 1003): 28071.12,11728.57 28083.12,11716.57 28083.12,11162.57 28072.12,11151.57 27497.12,11151.57 27472.12,11176.57 27472.12,11708.57 27492.12,11728.57
DGND on Top Layer "TOP-No Net" (solid, remove dead copper, pour order 1001): 28302.62,11363.07 28312.62,11353.07 28312.62,11215.57 28302.62,11205.57 28107.62,11205.57 28100.12,11213.07 28100.12,11353.07 28110.12,11363.07
NetM1_2 on Top Layer "TOP-No Net" (solid, remove dead copper, pour order 1000): 18 vertices, not listed, extent 28077.62,10983.07 28277.62,11113.07
VDD_3V3B on Top Layer "Top Layer-No Net" (solid, remove dead copper, pour order 1008): 27587,14065.15 27673,14065.15 27679,14059.15 27679,13807.15 27668,13796.15 27588,13796.15 27583,13801.15 27583,14061.15
VDD_5V0 on Top Layer "Top Layer-No Net" (solid, remove dead copper, pour order 1003): 17 vertices, not listed, extent 25260,13305 25585,13575
VDD_PLL on Top Layer "Top Layer-No Net" (solid, remove dead copper, pour order 1001): 26255,13075 26270,13090 26270,13175 26260,13185 26110,13185 26095,13170 26095,13090 26110,13075
VDD_3V3B on Top Layer "TOP-No Net" (solid, remove dead copper, pour order 1000): 27500,12279 27605,12279 27615,12269 27615,12159 27595,12139 27500,12139 27485,12154 27485,12264
VDD_PHYA on Top Layer "TOP-No Net" (solid, remove dead copper, pour order 1001): 19 vertices, not listed, extent 27640,12144 27765,12394
VCCD_3V3A on Top Layer "Top Layer-No Net" (solid, remove dead copper, pour order 1002): 24676,12526 24770,12526 24773,12523 24773,12346 24763,12336 24679,12336 24666,12349 24666,12516
VDDS_DDR on Top Layer "TOP-No Net" (solid, remove dead copper, pour order 1003): 25400,12530 25410,12520 25540,12520 25555,12535 25555,12650 25545,12660 25410,12660 25400,12650
DGND on Top Layer "TOP-No Net" (solid, remove dead copper, pour order 1004): 25418.74,12485 25403.74,12470 25403.74,12410 25418.74,12395 25543.74,12395 25558.74,12410 25558.74,12470 25543.74,12485
DGND on Top Layer "TOP-No Net" (solid, remove dead copper, pour order 1005): 25555,12690 25560,12695 25560,12770 25550,12780 25425,12780 25410,12765 25410,12695 25415,12690
VCCD_3V3A on Top Layer "Top Layer-No Net" (solid, remove dead copper, pour order 1004): 24399,13099 24476,13099 24555,13020 24555,12894 24520,12859 24412,12859 24392,12879 24392,13092
VDD_1V8 on Top Layer "Top Layer-No Net" (solid, remove dead copper, pour order 1002): 26404.72,13048.9 26412.4,13041.22 26412.4,12972.4 26383.9,12943.9 26169,12943.9 26159,12953.9 26159,13030.9 26177,13048.9
NetC147_1 on Top Layer "TOP-No Net" (solid, remove dead copper, pour order 1002): 26747.62,11665.57 27380.12,11665.57 27407.62,11638.07 27407.62,11208.07 27702.62,10913.07 27957.62,10913.07 27975.12,10895.57 27975.12,10763.07 27970.12,10758.07 26765.12,10758.07 26727.62,10795.57 26727.62,11645.57
PWR_ARM on ART03 "TOP-No Net" (solid, remove dead copper, pour order 1000): 26910.4,14270.57 26926.84,14287.02 26926.84,14400.28 26906.55,14420.57 24954.12,14420.57 24913.12,14379.57 24913.12,14178.57 24683.12,13948.57 24683.12,13113.57 24750.12,13046.57 25202.12,13046.57 25233.12,13077.57 25233.12,14229.57 25274.12,14270.57
VDD_CORE on ART03 "TOP-No Net" (hatched 90Degree grid 5 track 5, remove dead copper, pour order 1034): 26393.23,12468.03 26606.93,12468.03 26629,12445.95 26629,12235 26619,12225 26403,12225 26386.27,12241.73 26386.27,12461.07
VDD_PHYA on ART03 "TOP-No Net" (solid, remove dead copper, pour order 1033): 27481,12568.62 27481,12311 27504,12288 27754.55,12288 27778.12,12311.57 27778.12,12569.57 27764.08,12583.62 27496,12583.62
NetD6_1 on ART03 "TOP-No Net" (solid, remove dead copper, pour order 1019): 28063.12,11390.57 28326.12,11390.57 28341.12,11375.57 28341.12,11040.57 28319.12,11018.57 28052.12,11018.57 28036.12,11034.57 28036.12,11363.57
VCCD_3V3A on ART03 "TOP-No Net" (solid, remove dead copper, pour order 1007): 24640.7,13073 24925.12,12788.57 24925.12,12381.57 24883.12,12339.57 24704.12,12339.57 24289,12754.7 24289,13042 24320,13073
VDD_5V0 on ART04 "TOP-No Net" (solid, remove dead copper, pour order 1020): 24718.12,11640.57 24745.12,11613.57 24745.12,11383.57 25271.09,10857.61 28192.09,10857.61 28220.12,10829.57 28220.12,10757.67 28194.06,10731.61 24835.09,10731.61 24374.12,11192.57 24374.12,11614.57 24400.12,11640.57
VDDS on ART04 "TOP-No Net" (solid, remove dead copper, pour order 1002): 29 vertices, not listed, extent 26384.12,12200.03 27236.71,13885.57
VDD_5V on ART04 "TOP-No Net" (solid, remove dead copper, pour order 1022): 25262.07,13446.72 25979.49,13446.72 26069.64,13536.87 26208.27,13536.87 26223.83,13521.31 26223.83,13236.62 26172.54,13185.33 25261.78,13185.33 25242.52,13204.59 25242.52,13427.17
VDD_1V8B on ART04 "TOP-No Net" (solid, remove dead copper, pour order 1021): 17 vertices, not listed, extent 24442.27,13517.57 25889.81,14000.76
PWR_ARM on ART04 "TOP-No Net" (solid, remove dead copper, pour order 1001): 28441.12,12901.57 28481.12,12941.57 28481.12,13835.57 27925.12,14391.57 26680.12,14391.57 26660.12,14371.57 26660.12,14273.57 26679.12,14254.57 27383.12,14254.57 28192.12,13445.57 28192.12,12930.57 28221.12,12901.57
DGND on Bottom Layer "TOP-No Net" (solid, remove dead copper, pour order 1020): 25370,12905 25550,12905 25565,12890 25565,12695 25555,12685 25374.99,12685 25360,12699.99 25360,12895
3V3_AUD on Bottom Layer "TOP-No Net" (solid, remove dead copper, pour order 1041): 17 vertices, not listed, extent 24487.89,13927.03 24646.85,14049.17
VDDS on Bottom Layer "TOP-No Net" (solid, remove dead copper, pour order 1040): 26651.12,13860.57 26762.12,13860.57 26773.12,13849.57 26773.12,13762.57 26765.12,13754.57 26652.12,13754.57 26642.12,13764.57 26642.12,13851.57
VDD_1V8 on Bottom Layer "TOP-No Net" (solid, remove dead copper, pour order 1039): 26618.12,13886.57 26628.12,13876.57 26628.12,13772.57 26619.12,13763.57 26555.12,13763.57 26544.12,13774.57 26544.12,13878.57 26552.12,13886.57
VDD_1V8B on Bottom Layer "Top Layer-No Net" (solid, remove dead copper, pour order 1016): 25512.12,13570.57 25862.12,13570.57 25889.12,13597.57 25889.12,13769.57 25874.7,13784 25493,13784 25477,13768 25477,13605.7
VDD_5V on Bottom Layer "TOP-No Net" (solid, remove dead copper, pour order 1038): 25328.2,13185.47 25317.2,13174.47 25213.2,13174.47 25199.2,13188.47 25199.2,13336.47 25211.2,13348.47 25312.7,13348.47 25328.2,13332.97
DGND on Bottom Layer "TOP-No Net" (solid, remove dead copper, pour order 1037): 19 vertices, not listed, extent 25675.12,13834.57 25916.12,14019.57
VDD_5V0 on Bottom Layer "TOP-No Net" (solid, remove dead copper, pour order 1036): 24573.12,13047.57 24548.17,13072.53 24548.17,13259.62 24568.12,13279.57 24760.16,13279.57 24779.16,13260.57 24779.16,13073.57 24753.16,13047.57
DGND on Bottom Layer "TOP-No Net" (solid, remove dead copper, pour order 1035): 18 vertices, not listed, extent 24824.12,13047.57 25031.12,13279.57
DGND on Bottom Layer "TOP-No Net" (solid, remove dead copper, pour order 1034): 20 vertices, not listed, extent 27032.12,11344.57 27485.12,11593.57
USB1_PWR on Bottom Layer "TOP-No Net" (solid, remove dead copper, pour order 1033): 28009.12,12168.57 28014.12,12163.57 28014.12,12074.57 28009.12,12069.57 27997.12,12069.57 27997,12069.7 27810,12069.7 27801.12,12078.57 27801.12,12161.57 27808.12,12168.57
DGND on Bottom Layer "TOP-No Net" (solid, remove dead copper, pour order 1032): 17 vertices, not listed, extent 28068.12,11605.57 28265.12,11813.57
SYS_5V on Bottom Layer "TOP-No Net" (solid, remove dead copper, pour order 1031): 17 vertices, not listed, extent 27864.12,11596.57 28032.12,11807.57
GND_EARTH on Bottom Layer "TOP-No Net" (solid, remove dead copper, pour order 1002): 23 vertices, not listed, extent 27959.43,13309 28594.43,14012
DGND on Bottom Layer "TOP-No Net" (solid, remove dead copper, pour order 1030): 24 vertices, not listed, extent 27406.12,10725.57 27636.12,10992.57
NetC149_1 on Bottom Layer "TOP-No Net" (solid, remove dead copper, pour order 1029): 34 vertices, not listed, extent 27030.12,11070.57 27807.62,11380.57
NetD6_1 on Bottom Layer "TOP-No Net" (solid, remove dead copper, pour order 1028): 24 vertices, not listed, extent 27857.62,11198.07 28085.12,11380.57
NetD6_1 on Bottom Layer "TOP-No Net" (solid, remove dead copper, pour order 1027): 28190.12,11160.57 28180.12,11150.57 28180.12,11048.07 28180.12,11003.07 28187.62,10995.57 28197.62,10995.57 28335.12,10995.57 28345.12,11005.57 28345.12,11035.57 28345.12,11145.57 28345.12,11150.57 28335.12,11160.57 28190.12,11160.57
VDD_5V0 on Bottom Layer "TOP-No Net" (solid, remove dead copper, pour order 1026): 28055.12,10840.57 28045.12,10830.57 28045.12,10820.57 28045.12,10740.57 28045.12,10738.07 28052.62,10730.57 28077.4,10730.57 28150.12,10730.57 28155.12,10735.57 28155.12,10740.57 28155.12,10833.07 28147.62,10840.57 28055.12,10840.57
NetM1_4 on Bottom Layer "TOP-No Net" (solid, remove dead copper, pour order 1025): 28067.62,11183.07 28122.62,11183.07 28160.12,11145.57 28160.12,11115.57 28157.62,11113.07 28085.12,11113.07 28052.62,11080.57 27997.62,11080.57 27992.62,11085.57 27992.62,11108.07
NetM1_2 on Bottom Layer "TOP-No Net" (solid, remove dead copper, pour order 1024): 28107.62,11103.07 28152.62,11103.07 28160.12,11103.07 28162.62,11100.57 28162.62,11090.57 28162.62,11003.07 28155.12,10995.57 28112.62,10995.57 28090.12,10995.57 28082.62,11003.07 28082.62,11020.57 28082.62,11090.57 28092.62,11100.57 28095.12,11103.07 28107.62,11103.07
NetC147_1 on Bottom Layer "TOP-No Net" (solid, remove dead copper, pour order 1023): 25 vertices, not listed, extent 27695.12,10730.57 28030.12,11005.57
DGND on Bottom Layer "TOP-No Net" (solid, remove dead copper, pour order 1001): 27586,12965 27612,12939 27612,12690 27587,12665 27255,12665 27231,12689 27231,12952 27244,12965
NetC241_1 on Bottom Layer "Top Layer-No Net" (solid, remove dead copper, pour order 1016): 19 vertices, not listed, extent 24567,12840.94 24802,12981
VDDS_DDR on Bottom Layer "TOP-No Net" (solid, remove dead copper, pour order 1017): 25400,12530 25410,12520 25540,12520 25555,12535 25555,12650 25545,12660 25410,12660 25400,12650
DGND on Bottom Layer "TOP-No Net" (solid, remove dead copper, pour order 1018): 25418.74,12485 25403.74,12470 25403.74,12410 25418.74,12395 25543.74,12395 25558.74,12410 25558.74,12470 25543.74,12485
VDD_CORE on Bottom Layer "TOP-No Net" (solid, remove dead copper, pour order 1024): 26725,12882 26939,12882 26964,12907 26964,12965 26950,12979 26721,12979 26714,12972 26714,12893
DGND on Bottom Layer "TOP-No Net" (solid, remove dead copper, pour order 1003): 26401.14,13277.29 26472.76,13277.29 26477.69,13272.35 26477.69,13191.56 26471.25,13185.12 26403.89,13185.12 26386.47,13202.54 26386.47,13262.62
VDDS_DDR on Bottom Layer "TOP-No Net" (solid, remove dead copper, pour order 1004): 26509.6,13281.18 26509.62,13281.15 26579.4,13281.15 26592.2,13268.35 26592.2,13149.65 26584.12,13141.57 26502.12,13141.57 26494.34,13149.36 26494.34,13272.62 26496.22,13274.5
VDD_5V0 on Bottom Layer "Top Layer-No Net" (solid, remove dead copper, pour order 1015): 25130.12,13367.57 25425.12,13367.57 25445,13387.45 25445,13740 25435,13750 25121.55,13750 25104.12,13732.57 25104.12,13393.57
VDD_3V3C on Bottom Layer "TOP-No Net" (solid, remove dead copper, pour order 1005): 24504,13916.62 24924.08,13916.62 24951.12,13889.57 24951.12,13739.57 25058.12,13632.57 25058.12,13363.57 25045.12,13350.57 24911.12,13350.57 24893.12,13368.57 24893.12,13511.57 24668.12,13736.57 24525.12,13736.57 24490.12,13771.57 24490.12,13902.75
DGND on GND02 (split plane): 87 vertices, not listed, extent 23978.08,10652.67 28488.03,14380.48
GND_EARTH on GND02 (split plane): 283 vertices, not listed, extent 23978.01,10570.34 28639.33,14467.89
AGND_AUD on GND02 (split plane): 30 vertices, not listed, extent 23978.26,13189.67 25104.03,14380.48
VDD_5V0 on PWR05 (split plane): 158 vertices, not listed, extent 23988.03,10651.67 28391.03,13575.23
SYS_5V on PWR05 (split plane): 107 vertices, not listed, extent 25906.31,11575.14 28488.03,14380.48
VDD_3V3A on PWR05 (split plane): 77 vertices, not listed, extent 25745.56,11012.56 27234.56,13997.78
VDD_3V3B on PWR05 (split plane): 18 vertices, not listed, extent 27119.63,11575.14 27855.5,14061.82
VCCD on PWR05 (split plane): 29 vertices, not listed, extent 24662.56,11012.56 25730.44,12730.01
VDDS_DDR on PWR05 (split plane): 31 vertices, not listed, extent 25261.69,12067.44 26670.61,13311.01
VDD_3V3C on PWR05 (split plane): 56 vertices, not listed, extent 24467.22,13006.44 26020.91,14380.48
3V3_AUD on PWR05 (split plane): 45 vertices, not listed, extent 23988.26,13189.67 25104.03,14380.48
VDD_CORE on PWR05 (split plane): 28 vertices, not listed, extent 26385.96,12232.56 26950.56,13658.01

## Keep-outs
GND02:
  circle w80: c24351,13753.89 r12
  circle w80: c24114.78,13753.89 r12
  circle w80: c24351,13373.62 r12
  circle w80: c24114.78,13373.62 r12

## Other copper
Top Layer:
  rectangle net VDD_3V3B: 27568.31,12170 27608.98,12225.37
  rectangle net VDD_3V3B: 27535,12215.43 27597.23,12262.42
  rectangle net VDD_PHYA: 27676.76,12217.84 27704.9,12261.82
  rectangle net VDD_PHYA: 27660,12311.83 27700,12345.57
  rectangle net VDD_PHYA: 27642.59,12168 27678.02,12372
  rectangle net VDD_1V8B: 24515.22,13643.11 24629.74,13681.25
  rectangle net VDD_3V3A: 26370.12,13829.57 26452.12,13885.57
  rectangle net VDD_3V3A: 26420.12,13794.57 26453.12,13885.57
  rectangle net DGND: 26489.12,13795.57 26525.12,13887.57
  rectangle net VDD_1V8: 26554.12,13768.57 26621.12,13886.57
  rectangle net DGND: 26635.12,13718.57 26693.12,13742.57
  rectangle net VDD_5V: 26081.12,13526.57 26132.12,13562.57
  rectangle net VDD_5V: 26182.12,13528.57 26221.12,13566
  rectangle net 3V3_AUD: 24517.12,13965.57 24574.12,14001.57
  rectangle net 3V3_AUD: 24543.12,13975.57 24582.12,14022.57
  region net PWR_ARM: 24830.12,13226.57 24790.12,13226.57 24790.12,13109.57 24830.12,13109.57
  region net PWR_ARM: 24864.12,13189.57 24794.12,13189.57 24794.12,13138.57 24864.12,13138.57
  region net VDD_5V0: 24711.12,13224.57 24672.12,13224.57 24672.12,13105.57 24711.12,13105.57
  region net VDD_5V0: 24740.12,13190.57 24624.12,13190.57 24624.12,13140.57 24740.12,13140.57
  rectangle net VDD_1V8B: 24500.12,13645.57 24564.74,13679.57
  rectangle net VDD_1V8B: 24545.3,13663.57 24584.71,13706.57
  rectangle net VCCD: 24760.12,12605.57 24780.12,12660
  rectangle net VDD_3V3C: 24973.12,13417.57 25007.12,13471.57
  rectangle net VDD_3V3C: 24978.12,13461.57 25038.12,13497.57
  rectangle net DGND: 24869.12,13462.57 24923.12,13495.57
  rectangle net DGND: 24521.12,13573.57 24637.23,13612.57
  rectangle net NetD6_1: 27928.12,11617.57 28010.12,11691.57
  rectangle net NetD6_1: 27553.12,11171.57 27620.12,11456.57
  rectangle net NetD6_1: 27515.8,11259.57 28070.12,11380.57
  rectangle net NetM1_2: 28122.12,11057.57 28267.12,11101.57
  rectangle net NetM1_2: 28152.12,11005.57 28236.12,11084.57
  rectangle net DGND: 28120.12,11269.57 28274.12,11311.57
  rectangle net DGND: 28160.12,11227.57 28221.12,11336.57
  rectangle net NetC147_1: 26795.12,10951.23 26885.34,10990.57
  rectangle net NetC147_1: 26870.12,11483.07 27007.62,11578.07
  rectangle net NetC147_1: 26877.62,11073.07 27007.62,11163.07
  rectangle net NetC147_1: 26967.62,11080.57 27000.12,11085.57
  rectangle net NetC147_1: 27150.12,11155.57 27242.62,11455.57
  rectangle net NetC147_1: 26857.62,11225.57 27287.62,11398.07
  rectangle net VDD_3V3B: 27615,13999.15 27664,14033.15
  rectangle net VDD_3V3B: 27601,13973.15 27634,14065.15
  rectangle net DGND: 27469,14001.15 27514,14036.15
  rectangle net DGND: 27495,13968.15 27528,14063.15
  rectangle net DGND: 27481,13899.15 27519,13928.15
  rectangle net DGND: 27518,13872.15 27546,13958.15
  rectangle net VDD_3V3B: 27584,13854 27617.06,13964.15
  region net DGND: 24938.12,13437.57 24938.12,13471.57 24903.12,13471.57 24903.12,13437.57
  rectangle net VDD_3V3C: 25908.12,13327.77 25987.12,13467.77
  rectangle net VDD_3V3C: 25860.12,13350.57 26017.12,13414.57
  rectangle net VDD_3V3C: 25639,13330 25675,13460
  rectangle net VDD_3V3C: 25668,13366 25700,13426
  rectangle net DGND: 25715,13330 25763.12,13464
  rectangle net DGND: 25760,13370 25808,13424
  rectangle net VDD_5V0: 25545,13338.75 25580,13460
  rectangle net VDD_5V0: 25510,13365 25550,13425
  rectangle net VDD_5V0: 25395,13370 25450,13410
  rectangle net VDD_5V0: 25365,13315 25490,13365
  region net AGND_AUD: 24602.63,13896.62 24602.63,13931.62 24519,13931.62 24519,13896.62
  region net AGND_AUD: 24579,13876.12 24579,13896.62 24544,13896.62 24544,13876.12
  rectangle net VDD_3V3B: 27615,13897.15 27644,13932.15
  rectangle net VDD_5V: 26047,13546 26107,13586
  rectangle net VCCD_3V3A: 24695,12485 24766,12516
  rectangle net VCCD_3V3A: 24739.12,12348 24768,12514
  rectangle net VCCD_3V3A: 24705,12396 24768,12428
  rectangle net DGND: 24813,12355 24839,12422
  rectangle net DGND: 24824,12394.57 25005,12426
  region net VDD_3V3D: 25005,12463.57 25005,12496.57 24870.4,12496.57 24870.4,12463.57
  rectangle net VDD_3V3D: 24810,12487 24843,12608
  rectangle net VDD_3V3D: 24810,12475 24927,12496.57
  rectangle net VDD_3V3D: 24810,12575 24887,12608
  rectangle net VCCD: 24685,12568.57 24770,12616.57
  rectangle net VCCD_3V3A: 24502,12875 24536,13010
  rectangle net VCCD_3V3A: 24475,12924 24520,12973
  rectangle net NetC241_1: 24595,12878 24627.06,13005
  rectangle net NetC241_1: 24610,12916.61 24655,12967
  rectangle net VDD_1V8: 26587,13777 26615,13844
  rectangle net DGND: 26652.12,13718.57 26693.12,13808.57
  rectangle net VDD_CORE: 26718,13561 26754,13617
  rectangle net VDD_CORE: 26718,13591 26804,13625.57
  rectangle net VDD_MPU: 26712.06,13295 26808,13328
  rectangle net DGND: 25434,12699 25540,12725
  rectangle net DGND: 25471,12710 25506,12755
  rectangle net VDDS_DDR: 25435,12627 25550,12650
  rectangle net VDDS_DDR: 25473,12540 25502,12640
  rectangle net VDDS_DDR: 25428,12529 25540,12555
  rectangle net DGND: 25438,12455 25540,12485
  rectangle net DGND: 25473,12410 25505,12470
  rectangle net VDD_3V3D: 24899,12475 24927,12530
  region net DGND: 24578.1,13549.35 24578.1,13607.35 24549.1,13607.35 24549.1,13549.35
  rectangle net NetC241_1: 24681.8,12904 24713.06,12992.61
  rectangle net NetC241_1: 24659.5,12926 24681.8,12960.8
  text "TOP" at 28817.72,11907.35 h100
ART03:
  text "ART03" at 28813.72,11465.35 h100
ART04:
  text "ART04" at 28817.72,11247.35 h100
Bottom Layer:
  rectangle net VDD_5V0: 25200,13374.57 25330,13417.57
  rectangle net VDD_5V0: 25239.12,13394.87 25288.12,13440
  rectangle net VDD_5V: 25216.7,13297.47 25312.2,13340.47
  region net VDD_5V: 25235.2,13326.47 25235.2,13278.47 25285.2,13278.47 25285.2,13326.47
  region net DGND: 24960.12,13242.57 24875.12,13242.57 24875.12,13081.57 24960.12,13081.57
  region net DGND: 24999.12,13206.57 24842.12,13206.57 24842.12,13114.57 24999.12,13114.57
  region net VDD_5V0: 24706.12,13250.57 24624.12,13250.57 24624.12,13070.57 24706.12,13070.57
  region net VDD_5V0: 24758.12,13205.57 24590.12,13205.57 24590.12,13109.57 24758.12,13109.57
  rectangle net DGND: 27134.12,11371.57 27199.12,11481.57
  rectangle net DGND: 27330.12,11354.57 27410.12,11498.57
  rectangle net DGND: 27073.12,11401.57 27451.87,11451.57
  rectangle net USB1_PWR: 27853.12,12092.57 27893.12,12130.57
  rectangle net USB1_PWR: 27949.12,12077.57 27986.12,12127.57
  rectangle net USB1_PWR: 27811.12,12116.57 27980.12,12158.57
  rectangle net DGND: 28151.12,11615.57 28216.12,11774.57
  rectangle net DGND: 28107.12,11666.57 28251.12,11727.57
  rectangle net SYS_5V: 27953.12,11666.57 28006.12,11723.57
  rectangle net SYS_5V: 27897.12,11605.57 27961.12,11775.57
  rectangle net GND_EARTH: 28466.12,11459.57 28525.12,11563.57
  rectangle net GND_EARTH: 28502.12,11366.57 28566.12,11649.57
  rectangle net GND_EARTH: 28532.43,13339 28574.43,13429
  rectangle net GND_EARTH: 28528.43,13904 28572.43,13986.21
  rectangle net GND_EARTH: 28064.43,13940 28179.43,13964
  rectangle net GND_EARTH: 28092.43,13914 28145.43,13984
  rectangle net GND_EARTH: 27991.43,13762.23 28022.43,13839.23
  rectangle net GND_EARTH: 27969.43,13784 28049.43,13818
  rectangle net GND_EARTH: 28139.43,13344 28199.43,13419
  rectangle net NetC147_1: 27919.12,10951.57 27969.12,10993.57
  rectangle net NetC147_1: 27958.12,10867.57 28011.12,10901.57
  rectangle net NetC147_1: 27989.12,10740.57 28020.12,10930.57
  rectangle net NetC147_1: 27940.12,10770.57 28010.12,10814.57
  rectangle net VDD_5V0: 28077.4,10772.57 28136.12,10802.57
  rectangle net NetC147_1: 27767.12,10743.57 27830.12,10904.57
  rectangle net NetC147_1: 27717.12,10793.61 27859.29,10852.57
  rectangle net DGND: 27514.12,10746.57 27576.12,10844.57
  rectangle net DGND: 27449.12,10782.57 27629.12,10850.57
  region net VDD_3V3C: 24628.4,13866.45 24628.4,13902.45 24528.4,13902.45 24528.4,13866.45
  region net VDD_3V3C: 24592.4,13836.45 24592.4,13870.45 24555.4,13870.45 24555.4,13836.45
  rectangle net VDD_1V8B: 25730,13595 25810,13745
  rectangle net VDD_1V8B: 25690,13635 25850,13710
  rectangle net VDD_1V8B: 25495,13610 25525,13735
  rectangle net VDD_1V8B: 25520,13645 25550,13700
  rectangle net VDD_5V0: 25402.66,13610.34 25434.66,13740.34
  rectangle net VDD_5V0: 25365,13646 25443.07,13699
  rectangle net GND_EARTH: 28092.43,13677.79 28145.43,13747.79
  rectangle net GND_EARTH: 27991.43,13552.26 28022.43,13603.02
  rectangle net GND_EARTH: 27959.43,13547.79 28049.43,13581.79
  rectangle net VDD_5V0: 25211.69,13715 25340,13745
  rectangle net VDD_5V0: 25245,13680 25300,13715
  rectangle net NetC241_1: 24643,12929 24780,12960
  rectangle net DGND: 26407,13246 26464,13266
  rectangle net DGND: 26440,13205 26462,13261
  rectangle net VDDS_DDR: 26505,13201 26536,13272
  rectangle net VDDS_DDR: 26505,13244 26567,13272
  rectangle net DGND: 25364,12831 25430,12859
  rectangle net DGND: 25365,12792 25390,12888
  rectangle net DGND: 25431,12695 25546,12725
  rectangle net DGND: 25474,12710 25505,12755
  rectangle net VDDS_DDR: 25433,12629 25540,12655
  rectangle net VDDS_DDR: 25476,12540 25501,12640
  rectangle net VDDS_DDR: 25437,12530 25542,12555
  region net 3V3_AUD: 24591.4,13980.45 24591.4,14006.45 24556.4,14006.45 24556.4,13980.45
  region net 3V3_AUD: 24619.62,13950.45 24619.62,13973.45 24528.62,13973.45 24528.62,13950.45
  rectangle net DGND: 25731.12,13862.8 25808.12,14001.57
  rectangle net DGND: 25688.12,13887.8 25870,13960.6
  rectangle net NetC149_1: 27066.57,11143.07 27455.12,11196.17
  rectangle net NetC149_1: 27141.27,11114.82 27207.12,11224.9
  rectangle net NetC149_1: 27325.07,11085.33 27416.66,11257.34
  rectangle net NetC149_1: 27508.06,11180.79 27536.56,11214.99
  rectangle net NetC149_1: 27481.37,11168.8 27516.16,11193.99
  rectangle net NetC149_1: 27683.76,11241.35 27790.01,11294.48
  rectangle net NetC149_1: 27721.93,11254.76 27767.32,11331.62
  rectangle net NetD6_1: 27870.51,11238.56 27971.46,11292.07
  rectangle net NetD6_1: 27895.33,11207.67 27938.36,11347.79
  rectangle net NetD6_1: 28261.49,11120.24 28283.19,11150.59
  rectangle net NetD6_1: 28261.49,11012.4 28280.91,11043.48
  text "BOTTOM" at 28817.72,10807.35 h100
GND02 (plane layer: these items are gaps in the copper):
  lines w40: 23957.93,11107.57 24314.12,11107.57 24393.12,11028.57 24393.12,10678.57 24439.12,10632.57 28238.12,10632.57 28279.12,10673.57 28279.12,10926.57 28411.12,11058.57 28411.12,11756.57 28508.12,11853.57 28508.12,13898.57 28438.12,13968.57 28294.12,13968.57 28251.12,14011.57 28251.12,14314.57 28165.12,14400.57 24433.12,14400.57 24375.12,14342.57 24375.12,14020.57 24324.12,13969.57 23973.12,13969.57 ; 23957.98,11069.79 23957.98,13871.98 ; 23960.98,13169.57 24405.12,13169.57 24447.12,13211.57 24447.12,13708.59 24468.11,13729.57 25099.12,13729.57 25124.12,13754.57 25124.12,14400.57
  text "GND02" at 28817.72,11687.35 h100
